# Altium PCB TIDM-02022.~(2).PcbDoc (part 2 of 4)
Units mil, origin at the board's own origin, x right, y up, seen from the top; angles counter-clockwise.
Board outline 1448.82 x 2299.21 mil, 16 copper layers (Top Layer, GND1, PWR1, PWR2, PWR3, GND2, GND3/SIG1, SIG2, SIG3, GND3/SIG4, GND5, PWR4, PWR5, GND6, GND7, Bottom Layer), stack 148.806 mil thick; 257 components, 138 nets, 739 pads, 1147 vias.

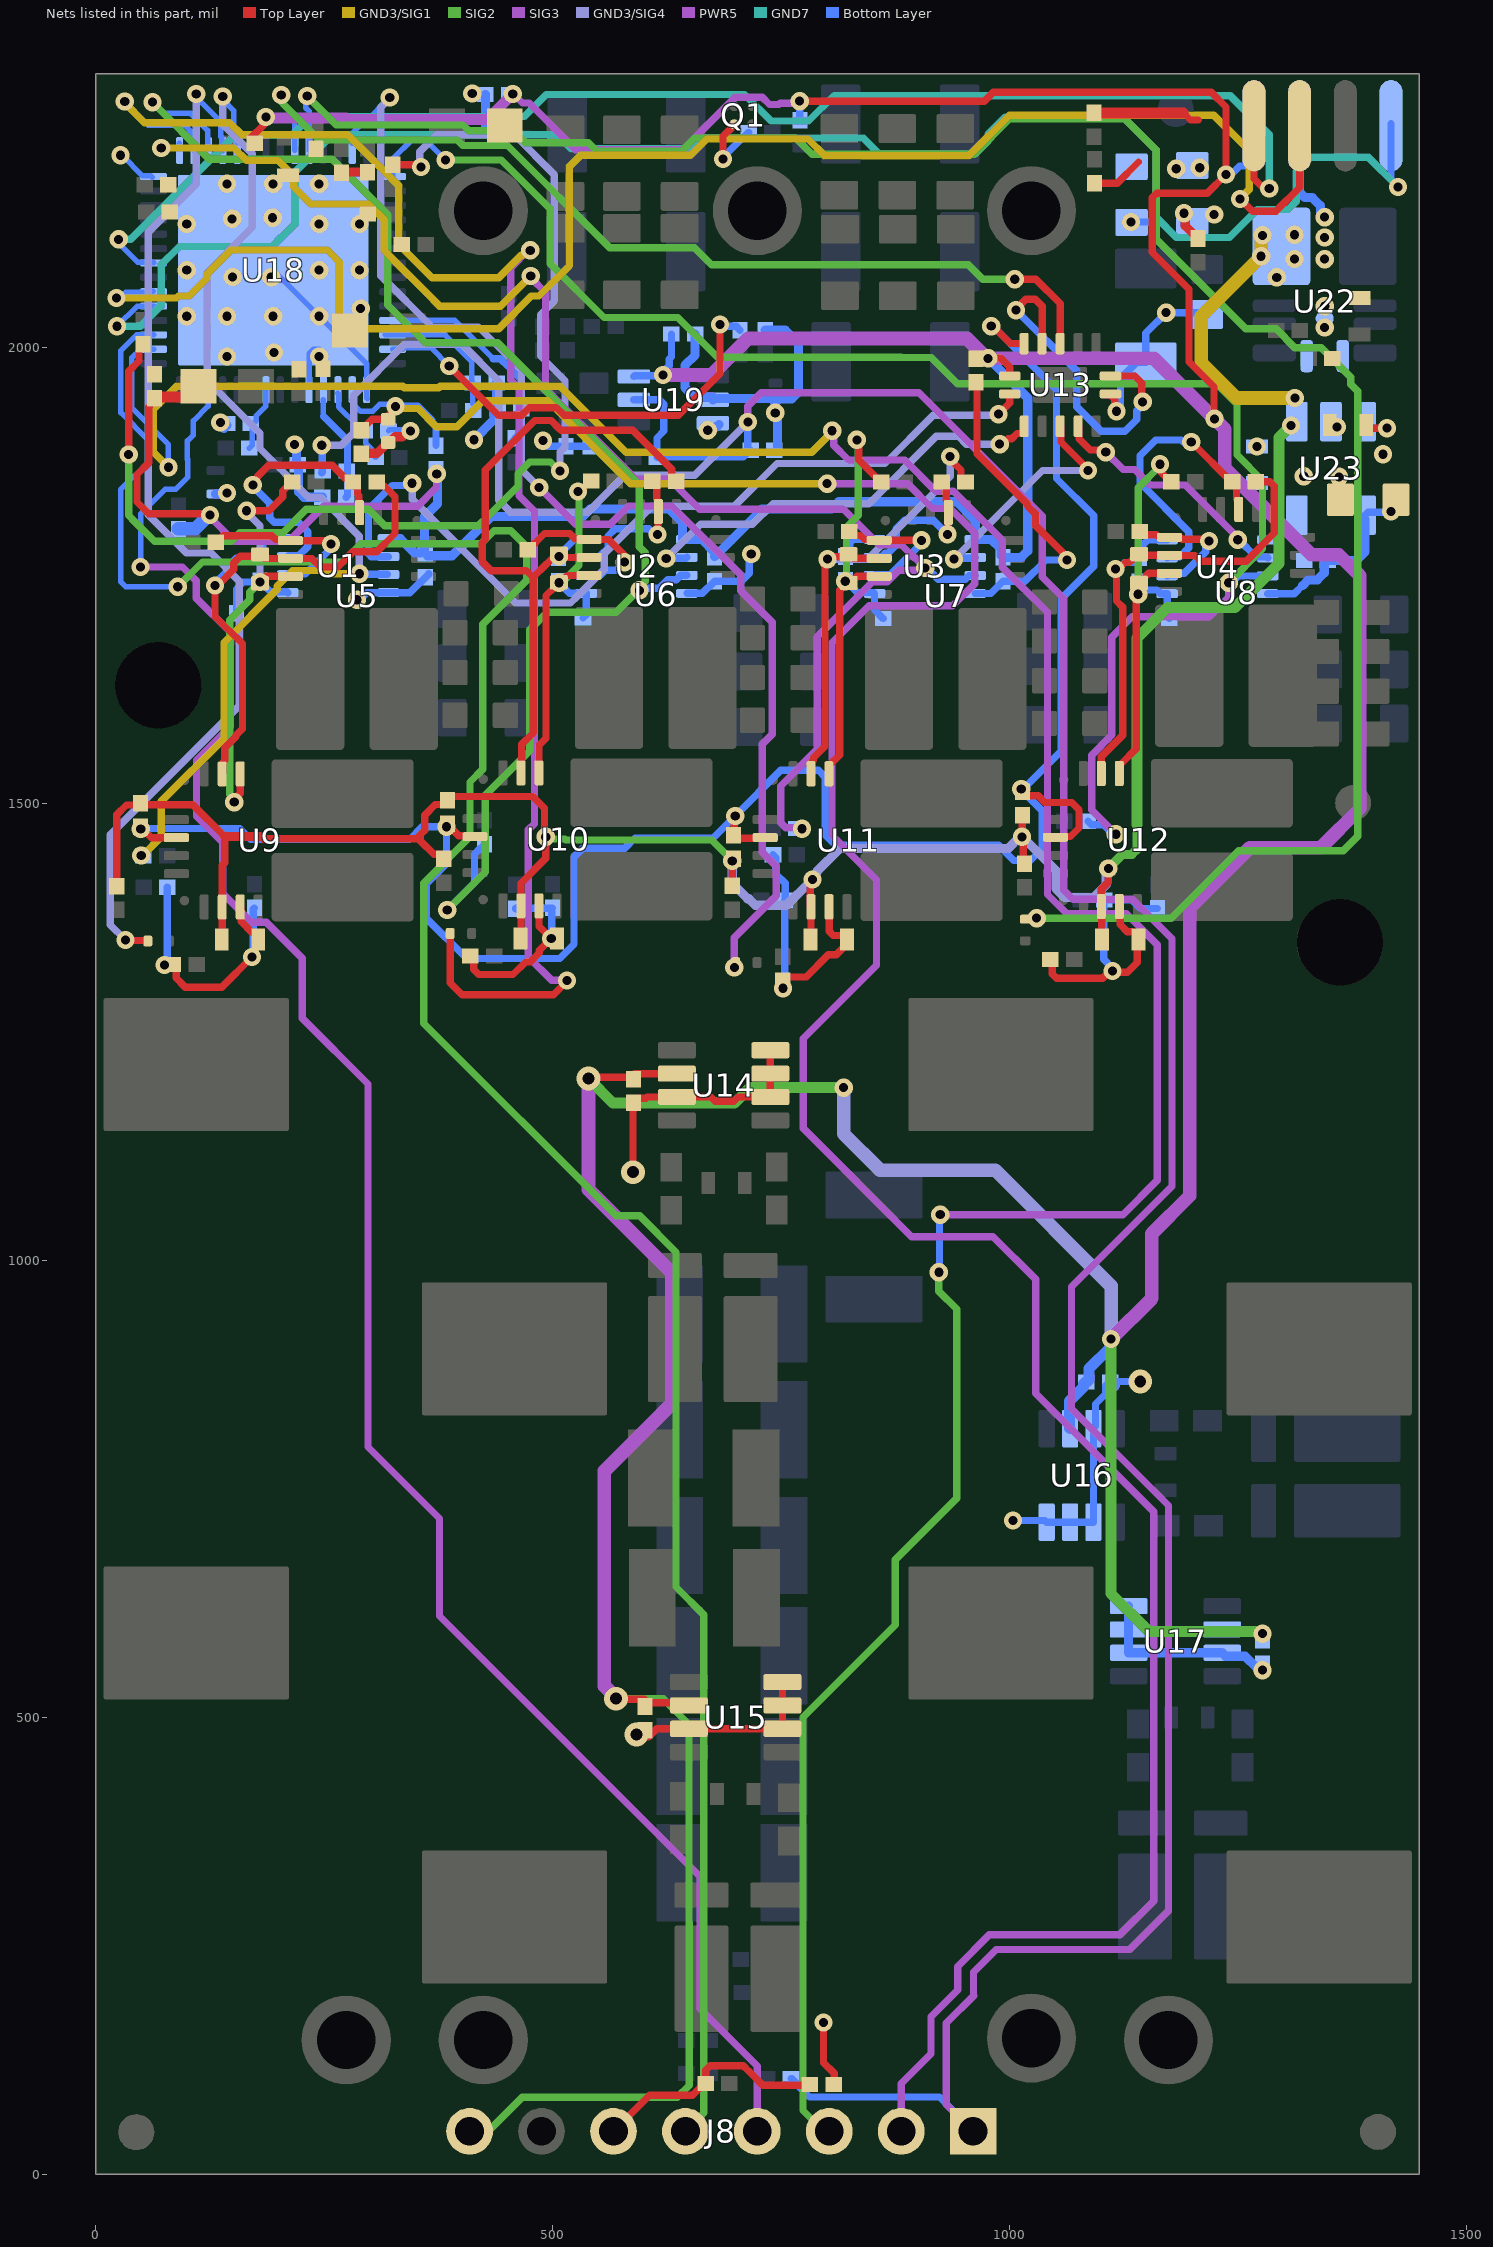
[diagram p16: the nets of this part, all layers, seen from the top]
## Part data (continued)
R33 R34 R35 R36 R41 R42 R43 R44: library part CMP-0025963-3, "RES, 10.0, 1%, 0.063 W, AEC-Q200 Grade 0, 0402", Manufacturer=Vishay-Dale, Power_W=63mW, Supplier Part Number 1=541-10.0LCT-ND, TempCo="100 ppm/C", Tolerance_%=1%, Value2=0.063W, Value_Code=10R0, ValueDisplayed=10.0
R37 R38 R39 R40: library part CMP-0083836-1, "RES, 100, 1%, 0.05 W, 0201", Manufacturer=Vishay-Semiconductor, Power_W=50mW, TempCo="100 ppm/C", Tolerance_%=1%, Value2=0.05W, Value_Code=100R, ValueDisplayed=100
R46: library part CMP-0026768-2, "RES, 100 k, 0.5%, 0.063 W, AEC-Q200 Grade 0, 0402", Manufacturer=Vishay-Dale, Power_W=63mW, Supplier Part Number 1=541-100KAVCT-ND, TempCo="50 ppm/C", Tolerance_%=0.5%, Value2=0.063W, Value_Code=100k
R47: library part CMP-0027657-1, "RES, 3.30 k, 1%, 0.05 W, 0201", Manufacturer="Yageo America", Power_W=50mW, Supplier Part Number 1=YAG2285CT-ND, TempCo="200 ppm/C", Tolerance_%=1%, Value2=0.05W, Value_Code=3k30, ValueDisplayed=3.30k
R49: library part CMP-0027789-1, "RES, 5.10 k, 1%, 0.05 W, 0201", Manufacturer="Yageo America", Power_W=50mW, Supplier Part Number 1=YAG2741CT-ND, TempCo="200 ppm/C", Tolerance_%=1%, Value2=0.05W, Value_Code=5k10, ValueDisplayed=5.10k
R55 R56 R58 R85 R86: library part CMP-0027995-1, "RES, 2.20 k, 1%, 0.05 W, 0201", Manufacturer="Yageo America", Power_W=50mW, Supplier Part Number 1=603-RC0201FR-7D2K2L, TempCo="200 ppm/C", Tolerance_%=1%, Value2=0.05W, Value_Code=2k20, ValueDisplayed=2.20k
R60: library part CMP-0027868-1, "RES, 768 k, 1%, 0.05 W, 0201", Manufacturer="Yageo America", Power_W=50mW, Supplier Part Number 1=YAG2796CT-ND, TempCo="200 ppm/C", Tolerance_%=1%, Value2=0.05W, Value_Code=768k
R61 R62: library part CMP-0027293-2, "RES, 100 k, 1%, 0.05 W, 0201", Manufacturer="Yageo America", Power_W=50mW, Supplier Part Number 1=311-100KMCT-ND, TempCo="200 ppm/C", Tolerance_%=1%, Value2=0.05W, Value_Code=100k
R65: library part CMP-0027793-1, "RES, 5.62 k, 1%, 0.05 W, 0201", Manufacturer="Yageo America", Power_W=50mW, Supplier Part Number 1=YAG2345CT-ND, TempCo="200 ppm/C", Tolerance_%=1%, Value2=0.05W, Value_Code=5k62, ValueDisplayed=5.62k
R66 R68: library part CMP-0027377-2, "RES, 15.0, 1%, 0.05 W, 0201", Manufacturer="Yageo America", Power_W=50mW, Supplier Part Number 1=311-15.0MCT-ND, TempCo="200 ppm/C", Tolerance_%=1%, Value2=0.05W, Value_Code=15R0, ValueDisplayed=15.0
R67: library part CMP-0027436-1, "RES, 1.43 k, 1%, 0.05 W, 0201", Manufacturer="Yageo America", Power_W=50mW, Supplier Part Number 1=YAG2481CT-ND, TempCo="200 ppm/C", Tolerance_%=1%, Value2=0.05W, Value_Code=1k43, ValueDisplayed=1.43k
R69: library part CMP-0027425-1, "RES, 1.13 k, 1%, 0.05 W, 0201", Manufacturer="Yageo America", Power_W=50mW, Supplier Part Number 1=YAG2471CT-ND, TempCo="200 ppm/C", Tolerance_%=1%, Value2=0.05W, Value_Code=1k13, ValueDisplayed=1.13k
R87: library part CMP-0027662-1, "RES, 3.60 k, 1%, 0.05 W, 0201", Manufacturer="Yageo America", Power_W=50mW, Supplier Part Number 1=YAG2651CT-ND, TempCo="200 ppm/C", Tolerance_%=1%, Value2=0.05W, Value_Code=3k60, ValueDisplayed=3.60k
R88: library part CMP-0126318-1, "22 kOhms ±0.5% 0.05W, 1/20W Chip Resistor 0201 (0603 Metric) Moisture Resistant Thick Film", Digikey Part Number=13-RC0201DR-0722KLCT-ND, Manufacturer=YAGEO, Mouser Part Number=603-RC0201DR-0722KL, Operating Temperature Range="-55°C to +125°C", Power_W=50mW, TempCo=200ppm/°C, Tolerance_%=0.5%
R91: library part CMP-0027792-1, "RES, 5.49 k, 1%, 0.05 W, 0201", Manufacturer="Yageo America", Power_W=50mW, Supplier Part Number 1=YAG2744CT-ND, TempCo="200 ppm/C", Tolerance_%=1%, Value2=0.05W, Value_Code=5k49, ValueDisplayed=5.49k
R92: library part CMP-0027939-1, "RES, 9.53 k, 1%, 0.05 W, 0201", Manufacturer="Yageo America", Power_W=50mW, Supplier Part Number 1=YAG2859CT-ND, TempCo="200 ppm/C", Tolerance_%=1%, Value2=0.05W, Value_Code=9k53, ValueDisplayed=9.53k
R93: library part CMP-0027453-1, "RES, 1.00 k, 1%, 0.05 W, 0201", Manufacturer="Yageo America", Power_W=50mW, Supplier Part Number 1=311-1KMCT-ND, TempCo="200 ppm/C", Tolerance_%=1%, Value2=0.05W, Value_Code=1k00, ValueDisplayed=1.00k
R94: library part CMP-0028000-1, "RES, 2.00 k, 1%, 0.05 W, 0201", Manufacturer="Yageo America", Power_W=50mW, Supplier Part Number 1=603-RC0201FR-7D2KL, TempCo="200 ppm/C", Tolerance_%=1%, Value2=0.05W, Value_Code=2k00, ValueDisplayed=2.00k
R95: library part CMP-0027973-1, "RES, 1.00 k, 1%, 0.05 W, 0201", Manufacturer="Yageo America", Power_W=50mW, Supplier Part Number 1=603-RC0201FR-7D1KL, TempCo="200 ppm/C", Tolerance_%=1%, Value2=0.05W, Value_Code=1k00, ValueDisplayed=1.00k
RT1: library part CMP-0123214-2, "±1% tolerance 10kΩ linear thermistor available in 0402 and 0603 package options 2-X1SON -40 to 125", Digikey Part Number=296-TMP6131DECRCT-ND, Manufacturer="Texas Instruments", Mouser Part Number=595-TMP6131DECR, Operating Temperature Range="-40°C to +125°C", Tolerance_%=1%
U1 U2 U3 U4: library part CMP-0123447-1, "General Purpose Dual-Channel Functional Isolators", Digikey Part Number=296-ISO6521FREURCT-ND, Manufacturer="Texas Instruments", Max Supply Voltage=5.5V, Min Supply Voltage=1.71V, Mouser Part Number=595-ISO6521FREUR, Operating Temperature Range="-40°C to +125°C"
U5 U6 U7 U8 U9 U10 U11 U12: library part CMP-0124166-1, Manufacturer="Texas Instruments", Operating Temperature Range=to
U13: library part CMP-0125756-1, "Four-channel two-input 1.65V to 3.6V AND gate 14-WQFN", Digikey Part Number=296-SN74LVC08ABQARCT-ND, Manufacturer="Texas Instruments", Max Supply Voltage=3.6V, Min Supply Voltage=1.65V, Mouser Part Number=595-SN74LVC08ABQAR, Nominal Supply Current=1uA, Operating Temperature Range="-40°C to +125°C"
U14 U15 U16 U17: library part CMP-0093651-2, "-4-V to 110-V, Bidirectional, Ultra-Precise Current Sense Amplifier With Enhanced PWM Rejection", Input Bias Current=40uA, Input Offset Voltage=0.002mV, Manufacturer="Texas Instruments", Max Supply Voltage=20V, Min Supply Voltage=2.7V, Nominal Supply Current=2.5mA, Operating Temperature Range="-40°C to +125°C", Voltage Gain=0.2V/mV
U18: library part CMP-0122591-1, "Real-Time Microcontrollers", Frequency_Fixed=150MHz, Manufacturer="Texas Instruments", Max Supply Voltage=3.63V, Min Supply Voltage=1.14V, Operating Temperature Range="-40°C to +150°C"
U19: library part CMP-0126255-1, "Low-power, 1-MΩ RIN, 20-µA IQ, small-size attenuating difference amplifier 6-SC70 -40 to 125", Digikey Part Number=296-INA500AIDCKRCT-ND, Manufacturer="Texas Instruments", Max Dual Supply Voltage=2.75V, Max Supply Voltage=5.5V, Min Dual Supply Voltage=850mV, Min Supply Voltage=1.7V, Mouser Part Number=595-INA500AIDCKR, Nominal Supply Current=13.5-14.5uA, Operating Temperature Range="-40°C to +125°C", Output Current Per Channel=33mA
U22: library part CMP-0098344-1, "3-V to 65-V Input, 1-V to 13-V Output, 600-mA Synchronous Buck Converter Power Module in a HotRod QFN Package", Manufacturer="Texas Instruments", Max Supply Voltage=65V, Min Supply Voltage=3.6V, Operating Temperature Range="-40°C to +125°C", Output Voltage=5V, Switching Frequency=1MHz
U23: library part CMP-0092532-1, "300-mA, Ultra-Low-Noise, Low-IQ, High PSRR LDO", Digikey Part Number=296-TPS7A2033PDBVRCT-ND, Dropout Voltage=145mV, Manufacturer="Texas Instruments", Max Supply Voltage=6V, Min Supply Voltage=1.6V, Mouser Part Number=595-TPS7A2033PDBVR, Nominal Supply Current=6.5uA, Operating Temperature Range="-40°C to +125°C", Output Voltage=3.3V

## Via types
v1: diameter 26, hole 13, Top Layer to Bottom Layer, tented both sides, 921 vias
v2: diameter 20, hole 10, Top Layer to Bottom Layer, tented both sides, 226 vias

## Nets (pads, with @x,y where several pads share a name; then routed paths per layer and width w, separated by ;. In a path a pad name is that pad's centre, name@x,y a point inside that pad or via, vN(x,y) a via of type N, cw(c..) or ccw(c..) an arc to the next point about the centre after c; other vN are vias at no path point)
3V3: 3V3.1 C49.1 C50.1 C51.1 C52.1 C81.1 C82.1 C83.1 C84.1 C94.1 C95.1 C124.1 C125.2 C147.1 C150.1 J8.8 L3.1 L4.1 R47.2 R55.2 R56.2 R87.2 U1.1 U2.1 U3.1 U4.1 U13.14 U14.6 U15.6 U16.6 U17.6 U19.6 U23.5 | length 8511.8
  Top Layer w8: C147.1@64.06,1944.15 59.8,1939.88 59.8,1936.23 57.98,1934.41 57.98,1873.42 45.21,1860.65 45.21,1830.43 58.1,1817.55 123.62,1817.55 v2(125.05,1816.12) ; R56.2@169.21,2228.56 v2@183.86,2243.21 ; v1(539.26,1199.37) 540.79,1200.91 586.55,1200.91 C81.1@588.75,1198.7 ; v1(569.56,520.58) 570.37,519.78 600.28,519.78 604,516.06 649.15,516.06 U15.6@649.25,515.96 ; C81.1@589.72,1204.74 U14.6@636.09,1204.74 ; v2(770.45,2269.26) 972.68,2269.26 982.55,2279.13 1220.99,2279.13 1237.17,2262.95 v2(1237.17,2188.94) 1216.8,2168.56 1161.18,2168.56 1156.5,2163.88 1156.5,2103.54 1196.69,2063.35 1196.69,1983.89 1223.96,1956.63 1223.96,1922.14 v2(1224.6,1921.5) ; v2@977.58,1988.13 990.66,1988.13 1000.51,1978.29 U13.14@1000.51,1968.45
  Top Layer w12: C147.1@64.06,1944.15 65.25,1945.34 109.77,1945.34 L3.1@114.37,1949.95 ; C95.1@963.51,1987.34 963.68,1987.52 976.61,1987.52 v2(976.79,1987.7)
  SIG3 w8: v2(125.05,1816.12) 125.05,1813.95 151.39,1787.61 211.21,1787.61 249.47,1825.88 352.35,1825.88 372.93,1846.46 372.93,1861.02 v2(373.21,1861.29) ; v2(456.46,2277.05) 457.24,2277.05 467.15,2267.14 474.49,2267.14 525.55,2216.08 642.66,2216.08 700.11,2273.53 729.52,2273.53 737.38,2265.67 747.6,2265.67 748.9,2266.97 768.15,2266.97 v2(770.45,2269.26)
  SIG3 w15: v1(539.26,1199.37) 539.26,1077.74 630.59,986.41 630.59,843.67 556.75,769.83 556.75,534.27 569.56,521.46 v1(569.56,520.58) ; v2(620.93,1969.38) 673.83,1969.38 713.82,2009.37 953.77,2009.37 975.44,1987.7 v2(976.79,1987.7) 1158.4,1987.7 v2(1224.6,1921.5) 1235.92,1910.18 1235.92,1867.49 1330.65,1772.76 1360.65,1772.76 1383.53,1749.88 1383.53,1494.62 1341.03,1452.12 1263.55,1452.12 1197.53,1386.1 1197.53,1071.1 1156.04,1029.61 1156.04,958.77 v2(1111.4,914.14)
  PWR5 w12: v2(186.16,2251.83) 187.21,2250.78 273.7,2250.78 275.41,2249.07 428.49,2249.07 v2(456.46,2277.05)
  SIG2 w8: J8.8@409.2,46.91 429.65,46.91 466.97,84.24 636.67,84.24 649.53,97.1 649.53,275.22 649.43,275.32 649.43,492.34 621.18,520.58 v1(569.56,520.58)
  SIG2 w12: v1(539.26,1199.37) 566.26,1172.37 699.33,1172.37 716.35,1189.39 v2(818.66,1189.39) ; v2(1111.4,914.14) 1111.4,635.46 1152.7,594.16 1269.01,594.16 1269.88,593.29 1275.54,593.29 v2(1277.07,591.76)
  GND3/SIG4 w15: v2(818.66,1189.39) 818.66,1138.97 858.53,1099.1 984.53,1099.1 1111.4,972.23 v2(1111.4,914.14)
  Bottom Layer w8: U19.6@588.94,1967.88 589.69,1968.63 620.18,1968.63 v2(620.93,1969.38) 620.93,1972.62 627.84,1979.54 627.84,1987.03 630.14,1989.33 C94.1@630.14,2014.26 ; v2(770.45,2269.26) 770.75,2268.97 770.75,2248.41 R55.2@771.04,2248.11 ; U17.6@1233,596.36 1272.47,596.36 v2(1277.07,591.76) ; v2@1241.57,2187.46 1252.33,2198.22 1256.67,2198.22 1267.8,2209.36 3V3.1@1267.8,2242.26
  Bottom Layer w10: U1.1@327.23,1790.23 333.45,1790.23 349,1774.68 C49.1@355.35,1774.68 ; R87.2@372.44,1858.78 374.02,1857.21 374.02,1828.61 359.85,1814.44 359.85,1775.02 363.21,1771.65 389.88,1771.65 432.85,1814.63 533.06,1814.63 541.05,1822.62 627.67,1822.62 642.33,1807.95 642.33,1790.44 643.25,1789.52 U2.1@647.07,1789.52 663.13,1789.52 C50.1@677.41,1775.24 ; C50.1@677.41,1770.64 729.38,1822.62 805.2,1822.62 813.29,1830.71 942.27,1830.71 962.68,1810.29 U3.1@962.68,1789.45 980.54,1789.45 990.75,1779.23 990.75,1772.05 C51.1@993.02,1769.79 1013.11,1769.79 1020.23,1776.9 1020.23,1944.27 v2(976.79,1987.7)
  Bottom Layer w12: U16.6@1066.49,816.09 1066.01,816.57 1066.01,846.41 1081.21,861.61 1081.21,865.05 1083.48,867.32 1085.06,867.32 1087.32,869.59 1087.32,881.88 v2@1109.87,904.43
  Bottom Layer w15: R47.2@90.44,1801.27 108.85,1801.27 123.7,1816.12 v2(125.05,1816.12)
  other v2: 1360.87,1858.03 1322.28,1858.71
5V: C66.1 C67.1 C68.1 C69.1 C121.2 C122.2 C123.1 R10.1 R12.1 R14.1 R16.1 R21.2 R22.2 R23.2 R24.2 R58.2 R62.1 U9.3 U10.3 U11.3 U12.3 U22.4 U22.9 U23.1 U23.3 | length 2925.2
  Top Layer w8: R10.1@22.9,1409.98 22.9,1488.03 33.63,1498.76 R21.2@44.95,1498.76 ; R21.2@47.83,1500.36 48.98,1499.21 106.2,1499.21 141.12,1464.3 141.12,1435.46 138.39,1432.73 U9.3@138.39,1387.23 138.39,1357.66 135.08,1354.36 C66.1@137.8,1351.63 ; 184.85,1461.85 350.6,1461.85 354.58,1465.83 355.33,1465.83 ; R12.1@380.84,1439.89 380.84,1440.67 376.58,1444.94 370.19,1444.94 355.33,1459.79 355.33,1465.83 ; R22.2@384.17,1502.91 380.53,1499.26 371.56,1499.26 360.04,1487.74 360.04,1471.29 355.33,1466.58 355.33,1465.83 ; R22.2@384.79,1504.19 388.69,1508.09 478.3,1508.09 491.25,1495.14 491.25,1465.21 v2(492.56,1463.89) 492.56,1440.43 465.45,1413.31 U10.3@465.45,1388.32 465.45,1358.75 462.14,1355.44 C67.1@464.86,1352.72 ; R14.1@696.76,1410.2 v2@696.76,1430.1 ; C68.1@782.93,1352.9 U11.3@782.93,1387.36 782.17,1388.12 782.17,1415.03 v2(784.46,1417.32) ; R16.1@1017.15,1435.28 1015.32,1437.11 1015.32,1462.56 v2(1013.99,1463.89) 1014.29,1464.2 1014.29,1482.35 1015.26,1483.31 R24.2@1017.69,1483.31 ; R58.2@1093.27,2179.45 1118.05,2179.45 1141.33,2202.73 ; U12.3@1100.69,1387.69 1100.69,1406.6 1108.36,1414.27 v2(1108.41,1429.34) v2(1108.41,1429.34) ; C69.1@1101.05,1352 U12.3@1101.05,1387.28 ; C123.1@1390.65,1914.81 1394.15,1911.31 v2(1413.45,1911.31)
  Top Layer w10: 141.12,1464.3 182.4,1464.3 184.85,1461.85 ; v2(1191.15,2146.56) 1192.59,2145.13 1192.59,2132.64 1202.27,2122.96 1203.06,2122.96 1206.33,2119.69 R62.1@1206.33,2118.9
  SIG2 w8: v2(492.56,1463.89) 494.86,1461.6 513.2,1461.6 514.39,1460.41 674.3,1460.41 696.73,1437.97 v2(696.73,1437.64)
  SIG2 w10: v2(1108.41,1429.34) 1123.83,1444.76 1134.14,1444.76 1140,1450.62 1140,1477.73
  SIG2 w12: 1139.55,1477.73 1139.55,1681.33 1173.16,1714.94 1246.91,1714.94 1295.19,1763.21 1295.19,1901.08 v2(1308.38,1914.27)
  GND3/SIG4 w10: v2(696.73,1437.64) 696.73,1412.91 713.5,1396.14 714.91,1396.14 722.05,1389 756.13,1389 v2@782.54,1415.41 ; v2(784.46,1417.32) 784.46,1420.03 789.46,1425.03 789.46,1426.3 814.26,1451.1 998.49,1451.1 1011.28,1463.89 v2(1013.99,1463.89) ; v2@1014.32,1463.89 1050.95,1427.26 1050.95,1407.35 1060.91,1397.38 1091.87,1397.38 1106.11,1411.62 1106.11,1427.04 v2(1108.41,1429.34)
  GND3/SIG1 w15: v2(1277.07,2122.36) 1275.68,2120.98 v2(1275.68,2099.45) 1210.06,2033.83 1210.06,1982.56 1248.38,1944.24 v2(1312.57,1944.24)
  Bottom Layer w8: C122.2@1134.83,2136.99 1158.56,2136.99
  other v2: 1408.93,1882.69 1292.73,2076.34 1312.1,2096.46 1312.1,2123.06 1133.19,2137.09 1224.22,2145.28
+3V3_MCU: R85.2 R86.2 | length 1305.6
  Top Layer w8: v2(35.98,1882.53) 35.98,1973.52 47.22,1984.76 47.22,1998.9 R85.2@51.49,2003.16 ; R86.2@325.04,2199.61 v2@356,2199.61
  SIG2 w8: v2(35.98,1882.53) 35.98,1815.78 42.82,1808.94 64.23,1787.53 148.13,1787.53 157.42,1796.83 204.85,1796.83 230.41,1822.38 298.47,1822.38 316.36,1804.49 418.75,1804.49 429.31,1815.05 429.54,1815.05 462.15,1847.66 462.15,1861.29 475.03,1874.18 497.84,1874.18 507.49,1864.53 v2(508.17,1864.53)
  GND3/SIG4 w8: v2(356,2197.24) 354.51,2198.72 354.51,2213.84 373.08,2232.4 458.41,2232.4 501.97,2188.85 501.97,2050.5 486.86,2035.39 486.86,1990.22 513.53,1963.56 513.53,1890.52 508.17,1885.16 v2(508.17,1864.53)
ADDR0: C98.1 J8.2 R87.1 R88.2 U18.16 | length 3231.2
  Top Layer w8: C98.1@290.58,1909.2 290.58,1909.99 294.85,1914.26 295.63,1914.26 302.58,1921.2 R88.2@320.17,1921.2 ; R88.2@317.82,1922.57 328.15,1932.89 v2(328.15,1935.14)
  SIG3 w8: v2(800.61,1850.55) 888.67,1850.55 915.82,1823.4 935.18,1823.4 962,1796.57 962,1740.87 937.87,1716.74 846.39,1716.74 805.9,1676.25 805.9,1465.72 854.63,1416.99 854.63,1323.46 774.33,1243.16 774.33,1144.79 892.85,1026.27 982.05,1026.27 1028.82,979.5 1028.82,854.62 1158.16,725.28 1158.16,299.14 1121.02,262 978,262 943.45,227.45 943.45,201.67 914.23,172.45 914.23,131.95 881.64,99.36 J8.2@881.64,46.91
  GND3/SIG1 w8: v2(328.15,1935.14) 330.44,1932.85 352.85,1932.85 372.76,1912.94 395.31,1912.94 423.59,1941.22 494.92,1941.22 585.59,1850.55 v2(800.61,1850.55)
  Bottom Layer w6: U18.16@280.81,1942.59 281.68,1941.72 281.68,1937.89 289.98,1929.59 303,1929.59 310.74,1937.32 v2@328.15,1937.32
  Bottom Layer w8: v2(328.15,1935.14) 352.6,1935.14 367.94,1919.8 367.94,1918.16 372.44,1913.66 R87.1@372.44,1892.25
AGND_RS-: J8.6 R51.1 R70.1 | length 265.1
  Top Layer w8: J8.6@566.68,46.91 606.05,86.29 653.09,86.29 663.44,96.63 663.44,97.42 667.71,101.69 R51.1@668.49,101.69 ; R51.1@668.34,99.47 R51.1@667.68,99.47 667.68,114.08 672.37,118.77 708.66,118.77 714.41,113.02 714.61,113.02 730.21,97.42 R70.1@781.76,97.42
ALERT: J8.4 U18.26 | length 2290.7
  SIG3 w8: v2(49.04,1759.35) 94.96,1759.35 109.97,1744.34 109.97,1725.27 147.04,1688.19 147.04,1584.82 110.31,1548.09 110.31,1486.58 139.01,1457.88 139.01,1401.89 170.46,1370.45 186.73,1370.45 226,1331.17 226,1265.4 298,1193.4 298,804.52 298,796.03 376.18,717.85 376.18,611.08 661.42,325.84 661.42,181.17 724.16,118.43 J8.4@724.16,46.91
  Bottom Layer w6: v2(49.04,1759.35) 49.04,1817.56 76.09,1844.61 87.77,1844.61 100.54,1857.38 100.54,1877.24 100.3,1877.48 100.3,1897.32 106.74,1903.76 106.74,1919.25 122.92,1935.43 122.92,1953.01 U18.26@123.26,1953.35
CLK: J8.3 U18.30 | length 3432.9
  SIG3 w8: v2(806.06,1908.4) 807.74,1906.71 807.74,1892.73 824.01,1876.46 885.39,1876.46 919.5,1842.35 938.85,1842.35 992.37,1788.83 992.37,1759.12 1041.8,1709.69 1041.8,1400.91 1063.05,1379.67 1128.24,1379.67 1162.03,1345.88 1162.03,1087.95 1124.47,1050.4 v2(924.37,1050.4)
  SIG2 w8: J8.3@802.9,46.91 796.91,46.91 774.09,69.73 774.09,500.28 875.03,601.22 875.03,672.51 942.32,739.8 942.32,947.15 922.85,966.62 v2(922.85,987.39)
  GND3/SIG1 w8: v2(79.54,1868.54) 63.13,1884.95 63.13,1931.65 88.62,1957.14 336.24,1957.14 337.71,1955.67 375.29,1955.67 376.9,1957.28 508.11,1957.28 580.36,1885.02 783.85,1885.02 806.06,1907.23 v2(806.06,1908.4)
  Bottom Layer w6: U18.30@63.22,1997.64 48.7,1997.64 39.46,1988.41 39.46,1933.29 79.54,1893.21 v2(79.54,1868.54)
  Bottom Layer w8: v2(922.85,987.39) 923.61,988.15 923.61,1049.64 v2(924.37,1050.4)
DACA: R94.1 U18.13 | length 494.1
  Top Layer w8: v2(386.88,1979.28) 440.89,1925.27 466.26,1925.27 474.59,1933.61 504.41,1933.61 512.75,1925.27 637.63,1925.27 683.23,1970.87 v2(683.23,2024.81)
  Bottom Layer w6: U18.13@325.04,1997.64 335.86,1997.64 337.67,1999.46 366.71,1999.46 v2(386.88,1979.28)
  Bottom Layer w8: v2(683.23,2024.81) 685.31,2022.73 700.95,2022.73 705.22,2018.46 R94.1@705.22,2018.4
DATA: J8.5 U18.31 | length 2732.4
  SIG2 w8: v2(89.72,1737.72) 116.82,1764.83 270.32,1764.83 290.26,1784.77 421.66,1784.77 435.94,1799.05 454.16,1799.05 471.74,1781.47 471.74,1744.79 423.69,1696.74 423.69,1538.01 409.67,1523.99 409.67,1463.89 359.07,1413.3 359.07,1259.56 569.56,1049.07 595.43,1049.07 635.14,1009.36 635.14,642.81 665.43,612.53 665.43,281.95 665.53,281.85 665.53,67.02 J8.5@645.42,46.91
  Bottom Layer w6: U18.31@63.22,2013.39 44.65,2013.39 27.46,1996.21 27.46,1928.32 57.89,1897.88 57.89,1876.93 56.98,1876.01 56.98,1873.83 27.15,1844 27.15,1743.25 32.67,1737.72 v2(89.72,1737.72)
EPWM1A: R96.2 U1.3 U18.47 | length 1177
  GND3/SIG4 w8: v2(139.01,2274.26) 139.01,2243.69 171.12,2211.58 171.12,2149.71 171.28,2149.55 171.28,2131.33 121.89,2081.95 121.89,2043.14 121.74,2042.98 121.74,2024.75 121.89,2024.59 121.89,1999.04 121.74,1998.88 121.74,1980.66 121.89,1980.5 121.89,1963.57 179.68,1905.78 179.68,1888.93 233.27,1835.34 246.32,1835.34 288.55,1793.11 v2(288.55,1751.95)
  GND3/SIG1 w8: v2(49.76,1443.4) 51.22,1443.4 71.69,1463.87 71.69,1502.78 140.39,1571.48 140.39,1676.55 198.79,1734.96 198.79,1738.61 215.63,1755.45 255.05,1755.45 258.55,1751.95 v2(288.55,1751.95)
  Bottom Layer w6: v2(139.01,2274.26) 139.01,2270.84 151.16,2258.69 151.16,2240.18 154.76,2236.57 U18.47@154.76,2223.6
  Bottom Layer w8: v2(288.55,1751.95) 289.06,1751.44 318.89,1751.44 U1.3@319.07,1751.25
EPWM1B: R9.1 U18.46 | length 1167.5
  Top Layer w8: v2(32.49,1350.99) 33.05,1350.42 55.18,1350.42 R9.1@55.74,1350.99
  GND3/SIG4 w8: v2(32.49,1350.99) 16,1367.48 16,1466.35 157,1607.35 157,1743.84 126.1,1774.74 99.16,1774.74 57.53,1816.38 57.53,2125.82 109.95,2178.25 v2(109.95,2276.97)
  Bottom Layer w6: v2(109.95,2276.97) 109.95,2273.62 137.04,2246.53 137.04,2230.44 138.07,2229.41 138.07,2216.1 U18.46@139.01,2215.16
EPWM2A: R97.2 U2.3 U18.45 | length 1600
  SIG2 w8: v2(61.99,2268.12) 124.36,2205.76 258.8,2205.76 319.7,2144.86 319.7,2046.06 360.95,2004.81 439.9,2004.81 595.07,1849.64 595.07,1781.47 601.53,1775.01 601.53,1743.46 595.07,1737 v2(595.07,1733.75) 593.86,1733.75 569.8,1709.69 494.11,1709.69 475.03,1690.61 475.03,1558.07 426.31,1509.35 426.31,1425.48 v2@386.88,1386.05
  Bottom Layer w6: v2(61.99,2268.12) 74.15,2255.97 103.87,2255.97 122.45,2237.38 122.45,2223.98 U18.45@122.83,2223.6
  Bottom Layer w8: v2(384.68,1383.85) 414.61,1413.78 414.61,1445.23 420.36,1450.98 421.15,1450.98 425.41,1455.25 R97.2@425.41,1456.04 ; v2(595.07,1733.75) 597.36,1736.04 616.61,1736.04 625.95,1745.38 635.41,1745.38 640.18,1750.15 U2.3@647.07,1750.15
EPWM2B: R11.1 U18.44 | length 1729.3
  Top Layer w8: R11.1@387.9,1358.16 387.9,1303.99 400.94,1290.95 501,1290.95 515.75,1305.7 v2(515.75,1306.8)
  SIG3 w8: v2@474.83,2107.74 454.1,2087.01 454.1,1963.95 463.36,1954.68 463.36,1837.14 480.21,1820.29 480.21,1478.41 473.56,1471.76 473.56,1332.4 499.16,1306.8 v2(515.75,1306.8) ; v2@515.75,1311 v2@517.08,1311
  GND3/SIG1 w8: v2(31.65,2268.79) 31.65,2267.35 53.42,2245.58 146.44,2245.58 159.62,2232.4 275.99,2232.4 331.62,2176.76 331.62,2112.38 340.95,2103.05 368,2076 441,2076 465.7,2100.7 467.15,2100.7 472.36,2105.91 v2(475.61,2105.91)
  Bottom Layer w6: v2(31.65,2268.79) 57.36,2243.06 96.98,2243.06 106.7,2233.33 106.7,2215.98 U18.44@107.52,2215.16
EPWM3A: R98.2 U3.3 U18.43 | length 1631.6
  SIG3 w8: v2@476.1,2075.85 492.18,2059.76 492.18,1954.7 591.37,1855.51 627.98,1855.51 660.87,1822.62 818.46,1822.62 857.69,1783.4 882.01,1783.4 895.92,1769.49 897.15,1769.49 907.84,1758.8 v2(907.84,1758.32) 905.54,1756.03 897.4,1756.03 897.15,1755.78 879.1,1755.78 866.29,1742.98 850,1742.98 789.9,1682.88 789.9,1559.81 749.69,1519.61 749.69,1479.7 755.34,1474.06 v2@775.23,1474.06
  GND3/SIG1 w8: v2(71.69,2218) 151.39,2218 165.12,2204.27 199.72,2204.27 216.85,2187.14 216.85,2175.31 235.41,2156.75 298.2,2156.75 315.62,2139.33 315.62,2105.75 325.56,2095.82 361.37,2060 376.6,2044.77 442.97,2044.77 v2(476.1,2077.9)
  Bottom Layer w6: v2(71.69,2218) 90.83,2218 91.33,2218.5 U18.43@91.33,2223.39
  Bottom Layer w8: R98.2@767.59,1475.22 768.38,1475.22 772.65,1470.95 R98.2@772.65,1470.47 ; v2@908.86,1759.35 922.28,1745.93 951.65,1745.93 955.79,1750.08 U3.3@962.68,1750.08
  other v2: 773.16,1472.74
EPWM3B: R13.1 U18.55 | length 1351.5
  SIG3 w8: v2(485.36,1846.25) 525.49,1806.12 563.26,1806.12 583.17,1826.02 630.58,1826.02 705.93,1750.67 705.93,1733.2 740.38,1698.76 740.38,1576.13 729.69,1565.45 729.69,1446.95 745.02,1431.61 745.02,1399.55 699.03,1353.56 v2(699.03,1320.98)
  GND3/SIG4 w8: v2(321.74,2273.37) 321.74,2272.63 311.78,2262.68 311.78,2078.22 368,2022 419,2022 466,1975 466,1865.61 v2(485.36,1846.25)
  Bottom Layer w6: U18.55@280.74,2223.16 281.68,2224.1 281.68,2234.77 293.04,2246.13 294.51,2246.13 v2(321.74,2273.37)
EPWM4A: R99.2 U4.3 U18.1 | length 1811.2
  SIG3 w8: v2(1116.58,1466.76) 1090.07,1493.26 1090.07,1553.25 1112.21,1575.39 1112.21,1682.59 1134.37,1704.75 1218.83,1704.75 1240.16,1726.09 v2(1240.16,1742.13)
  SIG2 w8: v2(382.98,2204.76) 443.98,2204.76 497.61,2151.13 497.61,2091.21 556.36,2032.45 636.97,2032.45 680.48,1988.94 881.69,1988.94 882.06,1988.57 914.47,1988.57 943.29,1959.75 1226.87,1959.75 1249.19,1937.44 1249.19,1882.1 1277.19,1854.1 1277.19,1779.16 v2(1240.16,1742.13)
  Bottom Layer w6: U18.1@325.04,2186.62 325.04,2205.73 347.94,2228.63 359.25,2228.63 359.25,2228.48 v2(382.98,2204.76)
  Bottom Layer w8: R99.2@1086.05,1481.05 1090.05,1477.06 1103.03,1477.06 1113.33,1466.76 v2(1116.58,1466.76) ; v2(1240.16,1742.13) 1243.41,1742.13 1250.72,1749.44 1282.69,1749.44 U4.3@1282.98,1749.73
EPWM4B: R15.1 U18.52 | length 2330.9
  Top Layer w8: R15.1@1017.51,1373.76 1018.1,1374.35 1029.35,1374.35 v2(1029.94,1374.94)
  SIG2 w8: v2(231.5,2274.78) 263.19,2243.1 402.01,2243.1 408.35,2236.76 457.24,2236.76 470.26,2223.74 539.41,2223.74 548.44,2214.7 641.28,2214.7 655.48,2228.89 766.26,2228.89 784.06,2211.1 961.5,2211.1 1000.24,2249.84 1126.41,2249.84 1160.79,2215.46 1160.79,2117.95 1258.77,2019.97 1292.05,2019.97 1312.59,1999.42 1341.43,1999.42 1373.84,1967.01 1373.84,1959.31 1381.53,1951.62 1381.53,1464.59 1365.5,1448.56 1250.81,1448.56 1177.19,1374.94 v2(1029.94,1374.94)
  Bottom Layer w6: v2@229.85,2266.54 229.85,2261.99 233.58,2258.25 U18.52@233.58,2215.25
FLT1T: R1.2 U1.7 U5.13 | length 299.7
  Top Layer w8: v2(171.95,1849.1) 171.95,1852.35 177.35,1857.75 177.35,1858.81 189.18,1870.64 258.91,1870.64 273.1,1856.45 278.04,1856.45 286.45,1848.04 286.45,1838.94 287.86,1837.54 287.86,1819.83 U5.13@288.78,1818.91
  Bottom Layer w8: v2(171.95,1849.1) 171.95,1847.58 190.5,1829.03 190.5,1813.09 195.19,1808.41 221.81,1808.41 232,1798.22 232,1781.63 221.91,1771.54 211.11,1771.54 U1.7@210.19,1770.62
FLT1T-LS: U1.2 U13.1 | length 964
  Top Layer w8: v2@990.66,1929.08 v2(988.22,1926.64) 1000.51,1938.92 U13.1@1000.51,1948.76
  GND3/SIG4 w8: v2(346.29,1850.93) 346.29,1833.49 459.78,1720 519.73,1720 527,1727.27 556.65,1756.92 556.65,1773.74 608.61,1825.7 698.93,1825.7 745.79,1872.55 863.99,1872.55 916.71,1925.27 986.86,1925.27 v2(988.22,1926.64)
  Bottom Layer w8: U1.2@320.42,1770.62 301.57,1770.62 298.55,1773.64 298.55,1822.45 324.74,1848.63 343.99,1848.63 v2(346.29,1850.93)
FLT2T: R2.2 U2.7 U6.13 | length 160.9
  Top Layer w8: R2.2@610.14,1853.19 614.18,1849.15 614.18,1833.35 614.91,1832.62 614.91,1820.92 U6.13@615.84,1820 615.4,1819.57 615.4,1795.39 v2(614.97,1794.96)
  Bottom Layer w8: U2.7@536.83,1769.83 537.75,1770.75 547.49,1770.75 551.3,1770.75 552.58,1772.03 ; 553.15,1772.6 560.64,1780.09 ; 560.64,1780.89 560.64,1793.27 568.7,1801.33 605.36,1801.33 611.73,1794.96 v2(614.97,1794.96)
FLT2T-LS: U2.2 U13.2 | length 485.9
  Top Layer w8: v2(989.39,1893.77) 992.63,1893.77 998.47,1899.61 1002.53,1899.61 1008.44,1905.52 1015.33,1905.52 1016.25,1906.44 U13.2@1016.25,1913.33
  GND3/SIG4 w8: v2(624.51,1768.56) 661.95,1806 718.89,1806 741.44,1828.55 846.31,1828.55 920.1,1902.35 944.35,1902.35 952.93,1893.77 v2(989.39,1893.77)
  Bottom Layer w8: v2(624.51,1768.56) 624.86,1768.91 646.15,1768.91 U2.2@647.07,1769.83
FLT3T: R3.2 U3.7 U7.13 | length 174.6
  Top Layer w8: R3.2@926.06,1852.31 926.62,1852.31 930.89,1848.04 930.89,1832.82 932.39,1831.32 932.39,1819.96 U7.13@933.32,1819.04 932.86,1818.59 932.86,1795.5 v2(932.41,1795.05)
  Bottom Layer w8: U3.7@852.45,1769.76 853.37,1770.68 860.26,1770.68 864.1,1774.52 867.25,1774.52 876.26,1783.54 876.26,1801.24 885.5,1810.49 916.73,1810.49 932.17,1795.05 v2(932.41,1795.05)
FLT3T-LS: U3.2 U13.4 | length 272
  Top Layer w8: U13.4@1055.62,1913.33 1056.55,1912.41 1056.55,1896.21 1086.11,1866.65 v2(1086.11,1864.86)
  GND3/SIG4 w8: v2(939.39,1767.93) 1036.32,1864.86 v2(1086.11,1864.86)
  Bottom Layer w8: v2(939.39,1767.93) 940.31,1768.85 961.77,1768.85 U3.2@962.68,1769.76
FLT4T: R4.2 U4.7 U8.13 | length 314.9
  Top Layer w8: v2(1199.21,1896.23) 1199.4,1896.23 1243.03,1852.6 1244.48,1852.6 1248.75,1848.33 1248.75,1833.51 1250.15,1832.11 1250.15,1820.25 U8.13@1251.08,1819.33
  Bottom Layer w8: U4.7@1172.74,1769.41 1173.66,1770.34 1186.53,1770.34 1196.55,1780.36 1196.55,1797.84 1142.95,1851.44 1142.95,1880.93 1160.43,1898.41 1188.34,1898.41 1190.52,1896.23 v2(1199.21,1896.23)
FLT4T-LS: U4.2 U13.5 | length 276.3
  Top Layer w8: U13.5@1075.31,1913.33 1076.23,1912.41 1076.23,1899.55 1088.46,1887.32 1103.25,1887.32 v2(1105.55,1885.02)
  SIG3 w8: v2(1105.55,1885.02) 1124.62,1865.95 1137.43,1865.95 1154.2,1849.18 1192.53,1849.18 1250.03,1791.67 v2(1250.03,1789.16)
  Bottom Layer w8: v2(1250.03,1789.16) 1251.18,1789.16 1270,1770.34 1282.06,1770.34 U4.2@1282.98,1769.41
FLTB: R21.1 R22.1 R23.1 R24.1 U9.13 U10.13 U11.13 U12.13 U13.13 | length 2349.8
  Top Layer w8: R21.1@49.21,1473.23 49.21,1472.44 53.48,1468.17 55.75,1468.17 60.9,1463.02 U9.13@88.19,1463.02 ; v2(383.86,1474.94) 383.86,1477.27 R22.1@384.79,1478.21 ; R22.1@384.79,1477.42 397.19,1465.03 U10.13@413.39,1465.03 ; v2@698.82,1482.02 698.82,1465.97 702.27,1462.52 732.11,1462.52 U11.13@732.73,1463.15 ; v2(699.94,1486.85) 700.35,1486.43 v2@700.35,1482.02 ; v2(980.22,2022.95) 982.07,2022.95 1001.13,2003.88 U13.13@1016.25,2003.88 ; v2(1013.05,1516.39) 1013.05,1514.93 R24.1@1014.6,1513.39 1014.6,1512.6 1018.26,1508.95 1031.54,1508.95 1038.87,1501.62 1068.32,1501.62 1076.27,1493.67 1076.27,1473.69 1066.94,1464.36 1041.93,1464.36 U12.13@1040.94,1463.37
  Bottom Layer w8: v2(49.2,1472.49) 49.71,1473.01 157.5,1473.01 169.44,1461.06 343.43,1461.06 357.31,1474.94 v2(383.86,1474.94) 383.86,1434.3 361.86,1412.3 361.86,1374.91 406.05,1330.72 507.75,1330.72 523.58,1346.55 523.58,1442.08 533.01,1451.51 579.11,1451.51 590.25,1462.65 597.13,1462.65 ; 597.19,1462.65 675.74,1462.65 v2(699.94,1486.85) 749.8,1536.71 791.1,1536.71 798.64,1529.16 798.64,1466.06 810.13,1454.58 988.3,1454.58 995.01,1447.87 ; v2(980.22,2022.95) 982.07,2022.95 1051.7,1953.31 1051.7,1856.24 1092.27,1815.67 1092.27,1795.44 1092.27,1759.98 1056.73,1724.43 1056.73,1557.98 1015.14,1516.39 v2(1013.05,1516.39) 1013.05,1515.52 1035.99,1492.58 1035.99,1450.93 1023.1,1438.04 1004.88,1438.04 995.04,1447.87
FLTGAN: U13.11 U18.51 | length 1062.4
  Top Layer w8: v2(1005.98,2074.35) 1028.94,2074.35 1055.63,2047.65 U13.11@1055.62,2003.88
  SIG2 w8: v2(203.03,2276.09) 205.33,2273.8 205.33,2266.07 244.64,2226.76 395.73,2226.76 401.73,2220.76 450.61,2220.76 562.47,2108.9 655.31,2108.9 674.05,2090.16 955.2,2090.16 971.01,2074.35 v2(1005.98,2074.35)
  Bottom Layer w6: v2(203.03,2276.09) 203.03,2267.58 217.63,2252.98 U18.51@217.63,2215.29
FLTT: U13.8 U13.12 | length 372.8
  Top Layer w8: v2(1007.4,2040.45) 1007.4,2041.66 1018.09,2052.35 1028.31,2052.35 1035.94,2044.71 U13.12@1035.94,2003.88 ; U13.8@1110.74,1968.45 1137.16,1968.45 1144.98,1960.63 v2@1144.98,1941.06
  Bottom Layer w8: v2(1007.4,2040.45) 1073.65,1974.2 1073.65,1934.67 1100.53,1907.8 1126.53,1907.8 1139.42,1920.69 1139.42,1930.35 1145.93,1936.86 v2(1145.93,1940.11)
GND: C49.2 C50.2 C51.2 C52.2 C66.2 C67.2 C68.2 C69.2 C70.2 C71.2 C72.2 C73.2 C81.2 C82.2 C83.2 C84.2 C89.2 C90.2 C91.2 C92.2 C93.2 C94.2 C95.2 C96.1 C97.2 C98.2 C103.2 C106.2 C114.2 C118.1 C119.1 C120.2 C121.1 C122.1 C123.2 C124.2 C125.1 C143.2 C144.2 C145.2 C146.2 C147.2 C148.2 C149.2 C150.2 C151.2 C152.2 C153.2 C154.2 C155.1 GND.1 NT1.1 Q1.A2 R49.1 R61.1 R70.2 R75.1 R76.1 R77.1 R78.1 R79.1 R80.1 R81.1 R82.1 R88.1 R92.1 R95.1 RT1.1 U1.4 U2.4 U3.4 U4.4 U9.4 U10.4 U11.4 U12.4 U13.7 U14.2 U14.3 U14.4 U14.7 U15.2 U15.3 U15.4 U15.7 U16.2 U16.3 U16.4 U16.7 U17.2 U17.3 U17.4 U17.7 U18.15 U18.19 U18.42 U18.57 U19.2 U19.3 U22.10 U22.11 U23.2 U23.4 | length 4610.9
  Top Layer w8: v2(75.28,1323.76) 75.35,1323.7 C70.2@81.31,1323.7 ; C70.2@84.34,1324.08 87.97,1320.45 87.97,1309.42 97.99,1299.4 137.94,1299.4 v2(170.99,1332.45) ; U9.4@158.08,1387.23 159,1386.31 159,1371.48 170.84,1359.63 174.3,1359.63 177.8,1356.13 C66.2@177.8,1351.63 174.3,1348.13 v2@174.3,1339.01 ; C155.1@279.48,2004.09 289.94,2014.55 C155.1@289.94,2035 ; C71.2@410.01,1333.44 413.57,1329.88 413.57,1318.71 419.11,1313.18 456.8,1313.18 470.62,1327 475.61,1327 485.36,1336.75 485.36,1339.44 v2(498.64,1352.72) 485.13,1366.23 U10.4@485.13,1388.32 ; v1(588.08,1096.92) 588.08,1165.03 C81.2@588.75,1165.7 ; C81.2@588.75,1172.71 588.75,1173.37 593.02,1177.64 601.99,1177.64 603.5,1179.15 U14.7@636.09,1179.15 673.01,1179.15 677.79,1174.37 698.5,1174.37 703.28,1179.15 U14.2@738.45,1179.15 U14.3@738.45,1204.74 U14.4@738.45,1230.33 ; v1(591.92,481.26) 594.21,478.98 605.58,478.98 614.16,487.55 U15.7@649.25,487.55 U15.2@751.62,487.55 ; v2(686.6,2205.9) 686.6,2230.68 698.35,2242.42 698.35,2243.5 Q1.A2@698.89,2244.05 ; U15.2@751.62,490.37 U15.3@751.62,513.14 U15.4@751.62,538.73 ; C72.2@756.03,1310.59 777.63,1310.59 801.84,1334.79 810.52,1334.79 818.84,1343.11 818.84,1343.76 C68.2@820.26,1345.18 ; v2(796.65,165.96) 796.65,122.04 808.28,110.4 R70.2@808.28,98.13 ; U11.4@802.73,1385.7 802.73,1360.57 807.42,1355.88 818.84,1355.88 C68.2@822.34,1352.38 ; C95.2@963.51,1961.36 964.57,1960.29 964.57,1883.33 1019.94,1827.95 1019.94,1825.99 1028.98,1816.95 1028.98,1804.59 1057.3,1776.27 1057.3,1776.18 1063.18,1770.29 v2(1063.18,1767.04) ; C73.2@1044.86,1329.66 1047.08,1327.43 1047.08,1313.81 1051.77,1309.13 1102.2,1309.13 1110.11,1317.03 v2(1112.89,1317.03) 1114.29,1315.64 1129.43,1315.64 1140.12,1326.33 C69.2@1140.12,1352.03 ; C114.2@1092.66,2256.46 C114.2@1093.37,2257.17 ; U13.7@1104.84,1947.7 1110.83,1947.7 1115.52,1943.01 1115.52,1931.7 v2(1117.42,1929.8) ; U12.4@1120.37,1393.09 1121.29,1392.17 1121.29,1367.92 1129.16,1360.05 1133.33,1360.05 1133.66,1359.72 1137.83,1359.72 1140.1,1357.45 C69.2@1140.1,1356.55 ; 1190.37,2256.46 1198.3,2248.53 1206.78,2248.53 ; C123.2@1350.65,1914.81 1356.29,1914.81 v2(1358.55,1912.55) 1359.33,1913.33 v2@1359.33,1913.72
  Top Layer w10: C153.2@268.93,2191.75 C151.2@297.38,2191.75 ; C98.2@290.58,1883.22 291.19,1883.83 307.99,1883.83 317.29,1893.13 317.29,1893.72 320.07,1896.5 R88.1@320.66,1896.5 ; R88.1@320.17,1895.61 321.15,1895.61 327.4,1901.86 335.43,1901.86 341.69,1908.11 v2(344.39,1908.11) ; C72.2@751.98,1306.54 752.18,1306.34 v2(752.18,1298.16) ; C68.2@822.34,1351.76 C68.2@822.34,1352.38
  Top Layer w12: C114.2@1092.66,2256.46 1190.37,2256.46
  Bottom Layer w6: v2(27.15,2210.1) 28.79,2210.1 51.33,2187.56 60.32,2187.56 U18.42@61.69,2186.18 ; U18.57@194.13,2084.26 v2(244.52,2033.87) 296.49,1981.9 U18.15@296.49,1953.35 296.49,1944.5 U18.15@297.43,1943.56 ; U18.19@233.5,1961.35 233.5,1992.93 238.34,1997.77 U18.57@244.52,1997.77 ; C92.2@320.42,1908.4 321.74,1909.72 v2@343.7,1909.72
  Bottom Layer w8: v2@78.07,1322.89 78.23,1323.06 78.23,1408.56 R79.1@78.4,1408.72 ; v2(170.99,1332.45) 172.29,1333.75 172.29,1384.79 R75.1@173.59,1386.09 ; v2(285.83,1723.46) 289.07,1723.46 296.61,1731 320.17,1731 U1.4@320.42,1731.25 343.59,1731.25 355.56,1743.21 356.34,1743.21 364.38,1751.25 C49.2@364.38,1752.04 ; R80.1@459.38,1385.28 459.78,1385.68 R76.1@499.49,1385.68 ; v2@490.05,1896.23 494.7,1891.59 C93.2@514.6,1891.59 R49.1@541,1891.59 ; v2(498.64,1352.72) 499.27,1353.35 499.27,1385.46 R76.1@499.49,1385.68 ; R76.1@499.89,1386.09 R76.1@499.49,1385.68 ; U2.4@647.07,1730.46 663.99,1730.46 C50.2@677.41,1743.87 706.89,1743.87 715.27,1752.25 715.27,1771.26 v2(717.56,1773.56) ; v2(686.6,2205.9) 686.6,2207.76 713.84,2235 C106.2@714.63,2235 ; R77.1@741.3,1444.3 744.29,1441.31 744.29,1428.99 745.02,1428.25 745.02,1422.69 754.6,1413.11 754.6,1394.85 R81.1@754.29,1394.54 754.21,1394.45 754.21,1300.19 v2(752.18,1298.16) ; U3.4@962.68,1730.39 979.61,1730.39 C51.2@993.02,1743.8 1016.98,1743.8 1040.22,1767.04 v2(1063.18,1767.04) ; v2@1002.98,716.59 v2(1003.95,715.62) 1039.01,715.62 U16.4@1040.9,713.73 U16.3@1066.49,713.73 U16.2@1092.08,713.73 U16.7@1092.08,816.09 1094.38,818.39 1094.38,843.14 1105.32,854.08 1105.32,863.05 1109.59,867.32 C83.2@1110.25,867.32 ; v2(1112.89,1317.03) 1112.89,1320.28 1103.37,1329.8 1103.37,1394.2 R82.1@1104.02,1394.85 1133.93,1394.85 1143.25,1385.52 R78.1@1162.12,1385.52 ; C83.2@1116.01,861.57 1117.26,862.82 1117.26,867.32 1117.69,867.75 v1(1143.25,867.75) ; v2(1117.42,1929.8) 1117.42,1933.05 1121.69,1937.32 1121.69,1965.82 1139.44,1983.57 C118.1@1149.32,1983.57 1149.32,2015.45 v2(1171.64,2037.77) 1214.47,2037.77 C119.1@1216.68,2035.56 ; U4.4@1282.98,1730.04 1312.04,1730.04 1321,1739 ; U23.4@1389.51,1816.18 1392.64,1819.31 1417.12,1819.31 v2(1417.8,1820)
  Bottom Layer w10: RT1.1@131.14,1839.39 135.9,1839.39 135.98,1839.46 142.7,1839.46 v2(143.57,1840.33) ; C90.2@140.47,1911.26 C90.2@143.74,1914.53 ; v2@217.94,1893.17 219.85,1891.26 C103.2@219.85,1873.22 ; C103.2@221.25,1871.25 222.03,1871.25 222.03,1841.56 227.89,1835.7 C97.2@248.07,1835.7 ; v2(414.05,1898.67) 435.71,1920.34 435.71,1931.01 438.52,1933.83 C89.2@438.52,1961.35 ; C150.2@426.56,2276.56 426.56,2237.83 432.42,2231.97 NT1.1@451.71,2231.97 ; v1(588.08,1096.92) v1@590.05,1098.9 ; C94.2@656.12,2014.26 656.12,1991.27 644.84,1979.99 644.84,1955.77 653.61,1947.01 656.98,1947.01 658.82,1945.16 U19.2@675.56,1945.16 ; v2(669.83,1909.06) 672.83,1912.06 672.83,1912.59 679.47,1912.59 U19.3@682.35,1915.46 ; U19.2@675.56,1942.29 676.91,1943.64 C96.1@743.85,1943.64 ; R95.1@734.22,2017 R95.1@732.82,2018.4 754.64,2018.4 769.4,2003.65 769.4,1951.12 761.82,1943.53 752.24,1943.53 ; C96.1@743.96,1943.53 752.24,1943.53 ; R92.1@746.32,1887.16 746.32,1922.88 743.83,1925.36 v2(743.83,1928.06) 743.83,1941.67 743.24,1942.26 744.12,1942.39 752.24,1943.53 ; U17.4@1130.64,621.95 U17.3@1130.64,596.36 U17.2@1130.64,570.77 U17.7@1233,570.77 1236.74,567.03 1257.92,567.03 1271.28,553.67 1275.16,553.67 v2(1277.07,551.76) ; GND.1@1317.8,2244.76 GND.1@1317.8,2242.26 1317.8,2169.46 1323.66,2163.6 1331.59,2163.6 1340.43,2154.76 1340.43,2152.53 1340.6,2152.36 1340.6,2144.5 1343.43,2141.67 v2@1344.31,2141.67 ; 1321,1739 1327.24,1745.23 1337.16,1745.23 1344.78,1752.85 1344.78,1762.77 1346.63,1764.63 1346.84,1764.63 C52.2@1348.7,1766.5 1380.02,1766.5 1389.51,1775.99 U23.4@1389.51,1811.18
  other v2: 1271.19,1891.21 217.68,1893.31 489.5,1897.61 136.35,1917.54 143.74,1989.77 244.52,1989.77 195.02,1994.11 1345.18,2021.42 99.64,2033.87 143.74,2033.87 194.13,2033.87 289.94,2042.24 1345.33,2044.73 191.95,2076.49 149.79,2076.88 99.64,2084.26 244.52,2084.26 288.62,2084.26 1345.18,2096.27 1345.18,2120 99.64,2134.65 244.52,2134.65 288.62,2134.65 149.28,2140.44 193.64,2141.61 1345.18,2142.29 143.74,2178.75 194.13,2178.75 244.52,2178.75 1182.79,2195.21 1208.49,2196.34 412.17,2277.56
GPIO35/TDI: TDI.1 U18.36 | length 1556.1
  Top Layer w8: TDI.1@1267.8,2242.26 1267.8,2184.28 1276.28,2175.81 1282.23,2175.81 v2(1284.52,2173.51)
  GND7 w8: v2(25,2118) 38.41,2118 152.81,2232.4 215.34,2232.4 235.38,2252.44 469.06,2252.44 493.24,2276.62 710.06,2276.62 739.25,2247.43 780.26,2247.43 808.05,2275.22 1241.73,2275.22 1284.52,2232.43 v2(1284.52,2173.51)
  Bottom Layer w6: v2(25,2118) 27.68,2115.32 27.68,2111.07 45.78,2092.97 62.39,2092.97 U18.36@63.22,2092.13
GPIO37/TDO: TDO.1 U18.34 | length 1775.7
  Top Layer w8: v2(1252.52,2162.24) 1266.18,2148.57 1291.69,2148.57 1317.8,2174.69 TDO.1@1317.8,2242.26
  GND3/SIG1 w8: v2(22.71,2053.72) 88.39,2053.72 90.53,2055.87 102.36,2055.87 121.64,2075.15 121.64,2079.84 140.68,2098.88 140.9,2098.88 148.28,2106.26 253.64,2106.26 266.62,2093.28 266.62,2034.45 280.83,2020.24 441.07,2020.24 476.72,2055.9 485.21,2055.9 518.19,2088.88 518.19,2197.39 530.89,2210.1 650.98,2210.1 668.78,2227.9 779.52,2227.9 797.97,2209.45 955.72,2209.45 1000.21,2253.94 1223.83,2253.94 1262.52,2215.24 1262.52,2172.92 1252.52,2162.92 v2(1252.52,2162.24)
  Bottom Layer w6: v2(22.71,2053.72) 26.49,2053.72 32.8,2060.03 61.89,2060.03 U18.34@62.86,2061
HB1: C45.1 C53.2 R1.1 U1.8 U5.3 U9.9 | length 645.2
  Top Layer w8: U9.9@138.39,1532.9 139.31,1533.82 139.31,1545.59 141.15,1547.43 141.15,1561.46 153.15,1573.46 153.15,1574.82 160.51,1582.17 160.51,1675.3 130.58,1705.23 v2(130.58,1739.15) 133.34,1739.15 150.89,1756.7 150.89,1764.12 157.98,1771.21 178.05,1771.21 C53.2@179.82,1772.98 184.09,1768.71 U5.3@212.99,1768.71 236.29,1768.69 245.75,1759.23 264.72,1759.23 281.34,1775.85 307.42,1775.85 327.58,1796.01 327.58,1836.3 315.97,1847.91 311.78,1847.91 R1.1@307.51,1852.18
  Bottom Layer w8: v2(130.58,1739.15) 130.58,1741.6 147.74,1758.76 147.74,1763.11 153.54,1768.91 178.18,1768.91 C45.1@179.69,1770.42 ; C45.1@178.03,1768.77 182.78,1773.52 182.78,1785.62 187.47,1790.31 U1.8@210.19,1790.31
HB2: C46.1 C54.2 R2.1 U2.8 U6.3 U10.9 | length 748.4
  Top Layer w8: U10.9@465.45,1533.99 466.37,1534.91 466.37,1565.18 478.86,1577.67 478.86,1747.63 477.82,1748.67 ; v2(506.96,1770.7) 506.96,1773.98 C54.2@506.88,1774.07 504.91,1774.07 493.29,1762.45 493.22,1762.45 478.63,1747.86 471.44,1755.05 432.97,1755.05 423.05,1764.97 423.05,1786.16 426.31,1789.42 426.31,1865.53 480.39,1919.61 498.61,1919.61 506.95,1911.27 509.26,1908.96 587.87,1908.96 630.41,1866.42 630.41,1857.42 R2.1@634.56,1853.27 ; C54.2@511.14,1769.8 U6.3@540.05,1769.8
  Bottom Layer w8: C46.1@513.02,1778.57 523.97,1789.52 U2.8@536.83,1789.52
HB3: C47.1 C55.2 R3.1 U3.8 U7.3 U11.9 | length 596.8
  Top Layer w8: U11.9@783.85,1540.9 783.85,1545.65 785.69,1547.49 785.69,1550.63 798.32,1563.25 v2@798.32,1761.01 ; v2(800.95,1767.94) 800.95,1765.24 797.52,1761.81 800.49,1761.81 809.24,1770.56 821.33,1770.56 C55.2@824.05,1773.28 ; C55.2@824.36,1773.11 828.62,1768.84 U7.3@857.53,1768.84 ; v2(935.24,1880.35) 935.24,1877.42 947.12,1865.55 947.12,1856.58 951.38,1852.31 R3.1@952.05,1852.31
  GND3/SIG4 w8: v2(800.95,1767.94) 844.74,1767.94 935.24,1858.45 v2(935.24,1880.35)
  Bottom Layer w8: v2(800.95,1767.94) 801.76,1768.75 821.14,1768.75 825.52,1773.14 825.52,1785.87 829.1,1789.45 U3.8@852.45,1789.45
HB4: C48.1 C56.2 R4.1 U4.8 U8.3 U12.9 | length 583.1
  Top Layer w8: U12.9@1100.29,1533.72 1100.77,1534.2 1100.77,1551.75 1124.11,1575.08 1124.11,1715.29 1117.32,1722.07 1117.32,1756.05 v2(1116.18,1757.2) 1116.18,1757.58 1119.8,1757.58 1126.55,1764.32 1131.59,1764.32 1136.27,1769.01 1136.27,1769.52 1140.15,1773.39 C56.2@1142.12,1773.39 1143.38,1772.13 U8.3@1175.29,1772.13 ; U8.3@1175.52,1771.89 1203.23,1771.89 1209.44,1765.68 1259.18,1765.68 1290.02,1796.52 1290.02,1847.91 1285.33,1852.6 R4.1@1269.8,1852.6
  Bottom Layer w8: v2(1116.18,1757.2) 1119.42,1757.2 1126.51,1764.29 1137.98,1764.29 1142.24,1768.55 C48.1@1142.24,1769.21 1146.19,1773.16 1146.19,1783.57 1151.72,1789.1 U4.8@1172.74,1789.1
HO1: R17.2 U1.6 U5.2 | length 197.1
  Top Layer w8: R17.2@131.29,1786.44 132.08,1786.44 139.26,1793.61 192.72,1793.61 197.01,1789.32 212.07,1789.32 U5.2@212.99,1788.4 ; U5.2@213.28,1788.11 250.41,1788.11 254.13,1784.38 v2@258.38,1784.38
  Bottom Layer w8: U1.6@210.19,1750.94 211.11,1751.86 229.62,1751.86 255.09,1777.32 255.09,1782.61 v2@256.86,1784.38
  other v2: 257.38,1784.38
HO2: R18.2 U2.6 U6.2 | length 178.4
  Top Layer w8: R18.2@472.69,1778.17 473.48,1778.17 491.25,1795.94 518.76,1795.94 524.29,1790.41 539.13,1790.41 U6.2@540.05,1789.49 ; U6.2@540.16,1789.37 561.55,1789.37 578.65,1772.27 v2(578.65,1764.63)
  Bottom Layer w8: U2.6@536.83,1750.15 537.55,1750.87 552.66,1750.87 557.53,1755.74 569.76,1755.74 v2(578.65,1764.63)
HO3: R19.2 U3.6 U7.2 | length 151.8
  Top Layer w8: R19.2@824.96,1798.01 829.23,1793.74 837.12,1793.74 841.42,1789.45 856.61,1789.45 U7.2@857.53,1788.53 v2(903.79,1788.49)
  Bottom Layer w8: U3.6@852.45,1750.08 853.37,1751 869.4,1751 903.79,1785.39 v2(903.79,1788.49)
HO4: R20.2 U4.6 U8.2 | length 146.2
  Top Layer w8: R20.2@1143.51,1798.3 1147.02,1794.78 1157.49,1794.78 1157.69,1794.58 1160.82,1794.58 1162.66,1792.74 1174.37,1792.74 U8.2@1175.29,1791.81 ; U8.2@1174.37,1790.89 1188.1,1790.89 1189.26,1789.74 1216.5,1789.74 v2(1218.55,1787.68)
  Bottom Layer w8: U4.6@1172.74,1749.73 1173.66,1750.65 1183.4,1750.65 1185.24,1752.49 1191.31,1752.49 1214.97,1776.15 1214.97,1780.85 1218.55,1784.43 v2(1218.55,1787.68)
HS1: C45.2 C53.1 R5.1 R71.1 U1.5 U5.4 U9.8 | length 559
  Top Layer w8: v2(151.58,1501.9) 151.58,1505.15 158.08,1511.64 U9.8@158.08,1532.9 ; v2(165.16,1820.87) 189.56,1820.87 204.61,1835.91 204.61,1842.52 214.27,1852.18 R5.1@215.06,1852.18 ; C53.1@185.99,1749.03 U5.4@212.99,1749.03
  SIG2 w8: v2(151.58,1501.9) 151.58,1505.15 146.53,1510.21 146.53,1701.36 168.58,1723.41 168.58,1731.61 v2(179.79,1742.83)
  GND3/SIG4 w8: v2(165.16,1820.87) 165.16,1819.02 179.79,1804.39 v2(179.79,1742.83)
  Bottom Layer w8: R71.1@153.95,1708.76 153.95,1735.27 161.51,1742.83 v2(179.79,1742.83) 180.51,1742.83 191.16,1732.17 209.26,1732.17 U1.5@210.19,1731.25
HS2: C46.2 C54.1 R6.1 R72.1 U2.5 U6.4 U10.8 | length 446.3
  Top Layer w8: U10.8@485.13,1533.99 485.13,1564.14 492.86,1571.87 492.86,1728.03 501.04,1736.2 501.04,1738.7 504.46,1742.13 v2(506.96,1742.13) ; C54.1@506.88,1742.57 508.85,1742.57 516.39,1750.12 U6.4@540.05,1750.12 ; v2(527.76,1841.86) 529.92,1841.86 539.26,1851.2 R6.1@541.04,1851.2
  SIG2 w8: v2(506.96,1742.13) 509.95,1742.13 528.96,1761.14 528.96,1840.66 v2(527.76,1841.86)
  Bottom Layer w8: v2(506.96,1742.13) 507.07,1742.13 510.6,1738.59 510.6,1738.49 518.63,1730.46 U2.5@536.83,1730.46 536.83,1707 R72.1@533.34,1703.51
HS3: C47.2 C55.1 R7.1 R73.1 U3.5 U7.4 U11.8 | length 543.4
  Top Layer w8: U11.8@802.61,1533.03 803.53,1533.95 803.53,1542.81 814.21,1553.49 814.21,1733.91 824.05,1743.75 C55.1@824.05,1745.2 ; C55.1@826.02,1741.78 833.39,1749.16 U7.4@857.53,1749.16 ; v2(833.12,1898.46) 835.01,1896.57 835.01,1876.46 859.16,1852.31 R7.1@859.6,1852.31
  SIG2 w8: v2@820.42,1744.22 821.78,1745.58 821.78,1802.87 834.69,1815.78 834.69,1896.89 v2(833.12,1898.46)
  Bottom Layer w8: C47.2@820.42,1740.98 821.95,1742.5 821.95,1742.79 833.43,1731.31 851.52,1731.31 U3.5@852.45,1730.39 852.45,1712.53 R73.1@862.14,1702.84
  other v2: 820.42,1743.66
HS4: C48.2 C56.1 R8.1 R74.1 U4.5 U8.4 U12.8 | length 497.8
  Top Layer w8: U12.8@1120.37,1542.17 1121.29,1543.1 1121.6,1543.1 1138.92,1560.41 1138.92,1727.47 v2(1140.98,1729.53) 1140.98,1740.76 C56.1@1142.12,1741.9 1144.09,1741.9 1147.96,1745.77 1147.96,1747.74 1152.66,1752.44 U8.4@1175.29,1752.44 ; v2(1164.95,1871.82) 1164.95,1864.21 1175.96,1853.2 R8.1@1178.29,1853.2
  SIG2 w8: v2(1140.98,1729.53) 1140.98,1845.98 1164.95,1869.95 v2(1164.95,1871.82)
  Bottom Layer w8: v2(1140.98,1729.53) 1145.62,1734.18 1161.72,1734.18 1165.85,1730.04 U4.5@1172.74,1730.04 1172.74,1705.41 R74.1@1175.1,1703.05 ; C48.2@1142.24,1734.18 C48.2@1142.24,1743.23
IPh1: C89.1 R37.2 U18.12 | length 158.8
  Bottom Layer w6: U18.12@317.01,2013.48 382.38,2013.48 411.52,1984.34 411.52,1961.77 C89.1@412.73,1960.56 412.73,1938.24 R37.2@416.68,1934.28
IPh2: C90.1 R38.2 U18.22 | length 72.1
  Bottom Layer w6: R38.2@168.15,1889.41 171.35,1892.6 171.35,1913.69 170.51,1914.53 175.78,1919.79 175.78,1925 186.26,1935.48 U18.22@186.26,1953.35
IPh3: C91.1 R39.2 U18.11 | length 231.5
  Bottom Layer w6: U18.11@335.8,2029.2 337.08,2029.2 337.36,2029.49 392.73,2029.49 434.85,1987.37
  Bottom Layer w8: 434.85,1987.37 442.71,1987.37 451.25,1978.83 451.91,1978.83 465.75,1964.99 C91.1@465.75,1932.59 ; R39.2@454.55,1895.1 458.82,1899.36 R39.2@458.82,1900.15 463.09,1904.42 463.09,1908.02 464.96,1909.89 464.96,1928.32 466.11,1929.47 C91.1@466.11,1932.59
IPh4: C92.1 R40.2 U18.17 | length 88.5
  Bottom Layer w6: U18.17@265,1949.47 265.93,1948.53 265.93,1934.61 286.88,1913.66 289.17,1913.66 295.72,1907.11 295.72,1894.64 301.74,1888.62 301.74,1883.9 R40.2@306.25,1879.39
Ishare: C97.1 R93.1 U18.18 | length 118.5
  Bottom Layer w6: 249.18,1924.26 U18.18@249.18,1942.59
  Bottom Layer w8: 249.18,1924.26 269.48,1903.96 275.59,1897.85 275.59,1864.44 275.59,1837.24 C97.1@274.05,1835.7
Ishare_RS+: J8.1 R45.1 R91.1 R92.2 R93.2 U19.5 | length 3772.1
  SIG3 w8: v2(713.75,1917.93) 713.75,1935.3 728.52,1950.06 901.04,1950.06 1036.07,1815.03 1036.07,1748.4 1059.62,1724.85 1059.62,1405.72 1069.67,1395.67 1134.87,1395.67 1178.03,1352.51 1178.03,1081.32 1068.12,971.41 1068.12,837.95 1174.16,731.91 1174.16,288.49 1131.67,246 985.6,246 960.83,221.23 960.83,195.71 961.08,195.46 931.07,165.44 931.07,76.23 J8.1@960.38,46.91
  GND3/SIG4 w8: v2(247.34,1892.64) 268.87,1892.64 282.43,1906.2 282.43,1947.49 337.95,2003.01 400.99,2003.01 441.17,1962.83 441.17,1832.36 454.17,1819.35 538.64,1819.35 578.97,1859.68 655.5,1859.68 v2(713.75,1917.93)
  Bottom Layer w8: R93.2@247.34,1862.4 247.99,1863.05 247.99,1891.99 v2(247.34,1892.64) ; U19.5@588.94,1942.29 617.08,1942.29 621.77,1937.6 621.77,1908.12 614.24,1900.59 R91.1@614.24,1879.26 614.99,1880.01 708.84,1880.01 715.99,1887.16 R92.2@716.78,1887.16 ; R92.2@713.75,1887.16 v2(713.75,1917.93) ; R45.1@760.99,104.69 761.78,104.69 766.05,100.43 766.05,99.64 781.18,84.51 923.52,84.51 938.79,69.23 938.79,68.51 959.65,47.64 J8.1@960.38,47.64
MCU_TCK: TCK.1 U18.33 | length 1879
  GND7 w8: v2(23.33,2022.91) 23.53,2022.71 48.65,2022.71 71.69,2045.75 71.69,2090.35 91.55,2110.21 193.13,2110.21 202.53,2119.61 202.75,2119.61 218.29,2135.15 218.29,2191.93 258.76,2232.4 504.85,2232.4 520.17,2217.07 650.06,2217.07 661.88,2228.89 840.05,2228.89 857.5,2211.44 962.82,2211.44 976.56,2225.18 976.56,2233.12 995.21,2251.77 1124.78,2251.77 1160.79,2215.76 1160.79,2142.06 1182.85,2120 1240.66,2120 1271.25,2150.59 1305.03,2150.59 1313.95,2159.51 1313.95,2192.43 1329.23,2207.71 1393.04,2207.71 v2(1425.55,2175.21)
  Bottom Layer w6: v2(23.33,2022.91) 45.13,2044.71 63.05,2044.71 U18.33@63.22,2044.89
  Bottom Layer w8: TCK.1@1417.8,2244.76 TCK.1@1417.8,2242.26 1417.8,2183.89 1425.55,2176.15 v2(1425.55,2175.21) v2@1425.55,2173.21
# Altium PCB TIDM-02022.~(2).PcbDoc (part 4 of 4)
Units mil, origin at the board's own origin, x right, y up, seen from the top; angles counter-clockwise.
Board outline 1448.82 x 2299.21 mil, 16 copper layers (Top Layer, GND1, PWR1, PWR2, PWR3, GND2, GND3/SIG1, SIG2, SIG3, GND3/SIG4, GND5, PWR4, PWR5, GND6, GND7, Bottom Layer), stack 148.806 mil thick; 257 components, 138 nets, 739 pads, 1147 vias.

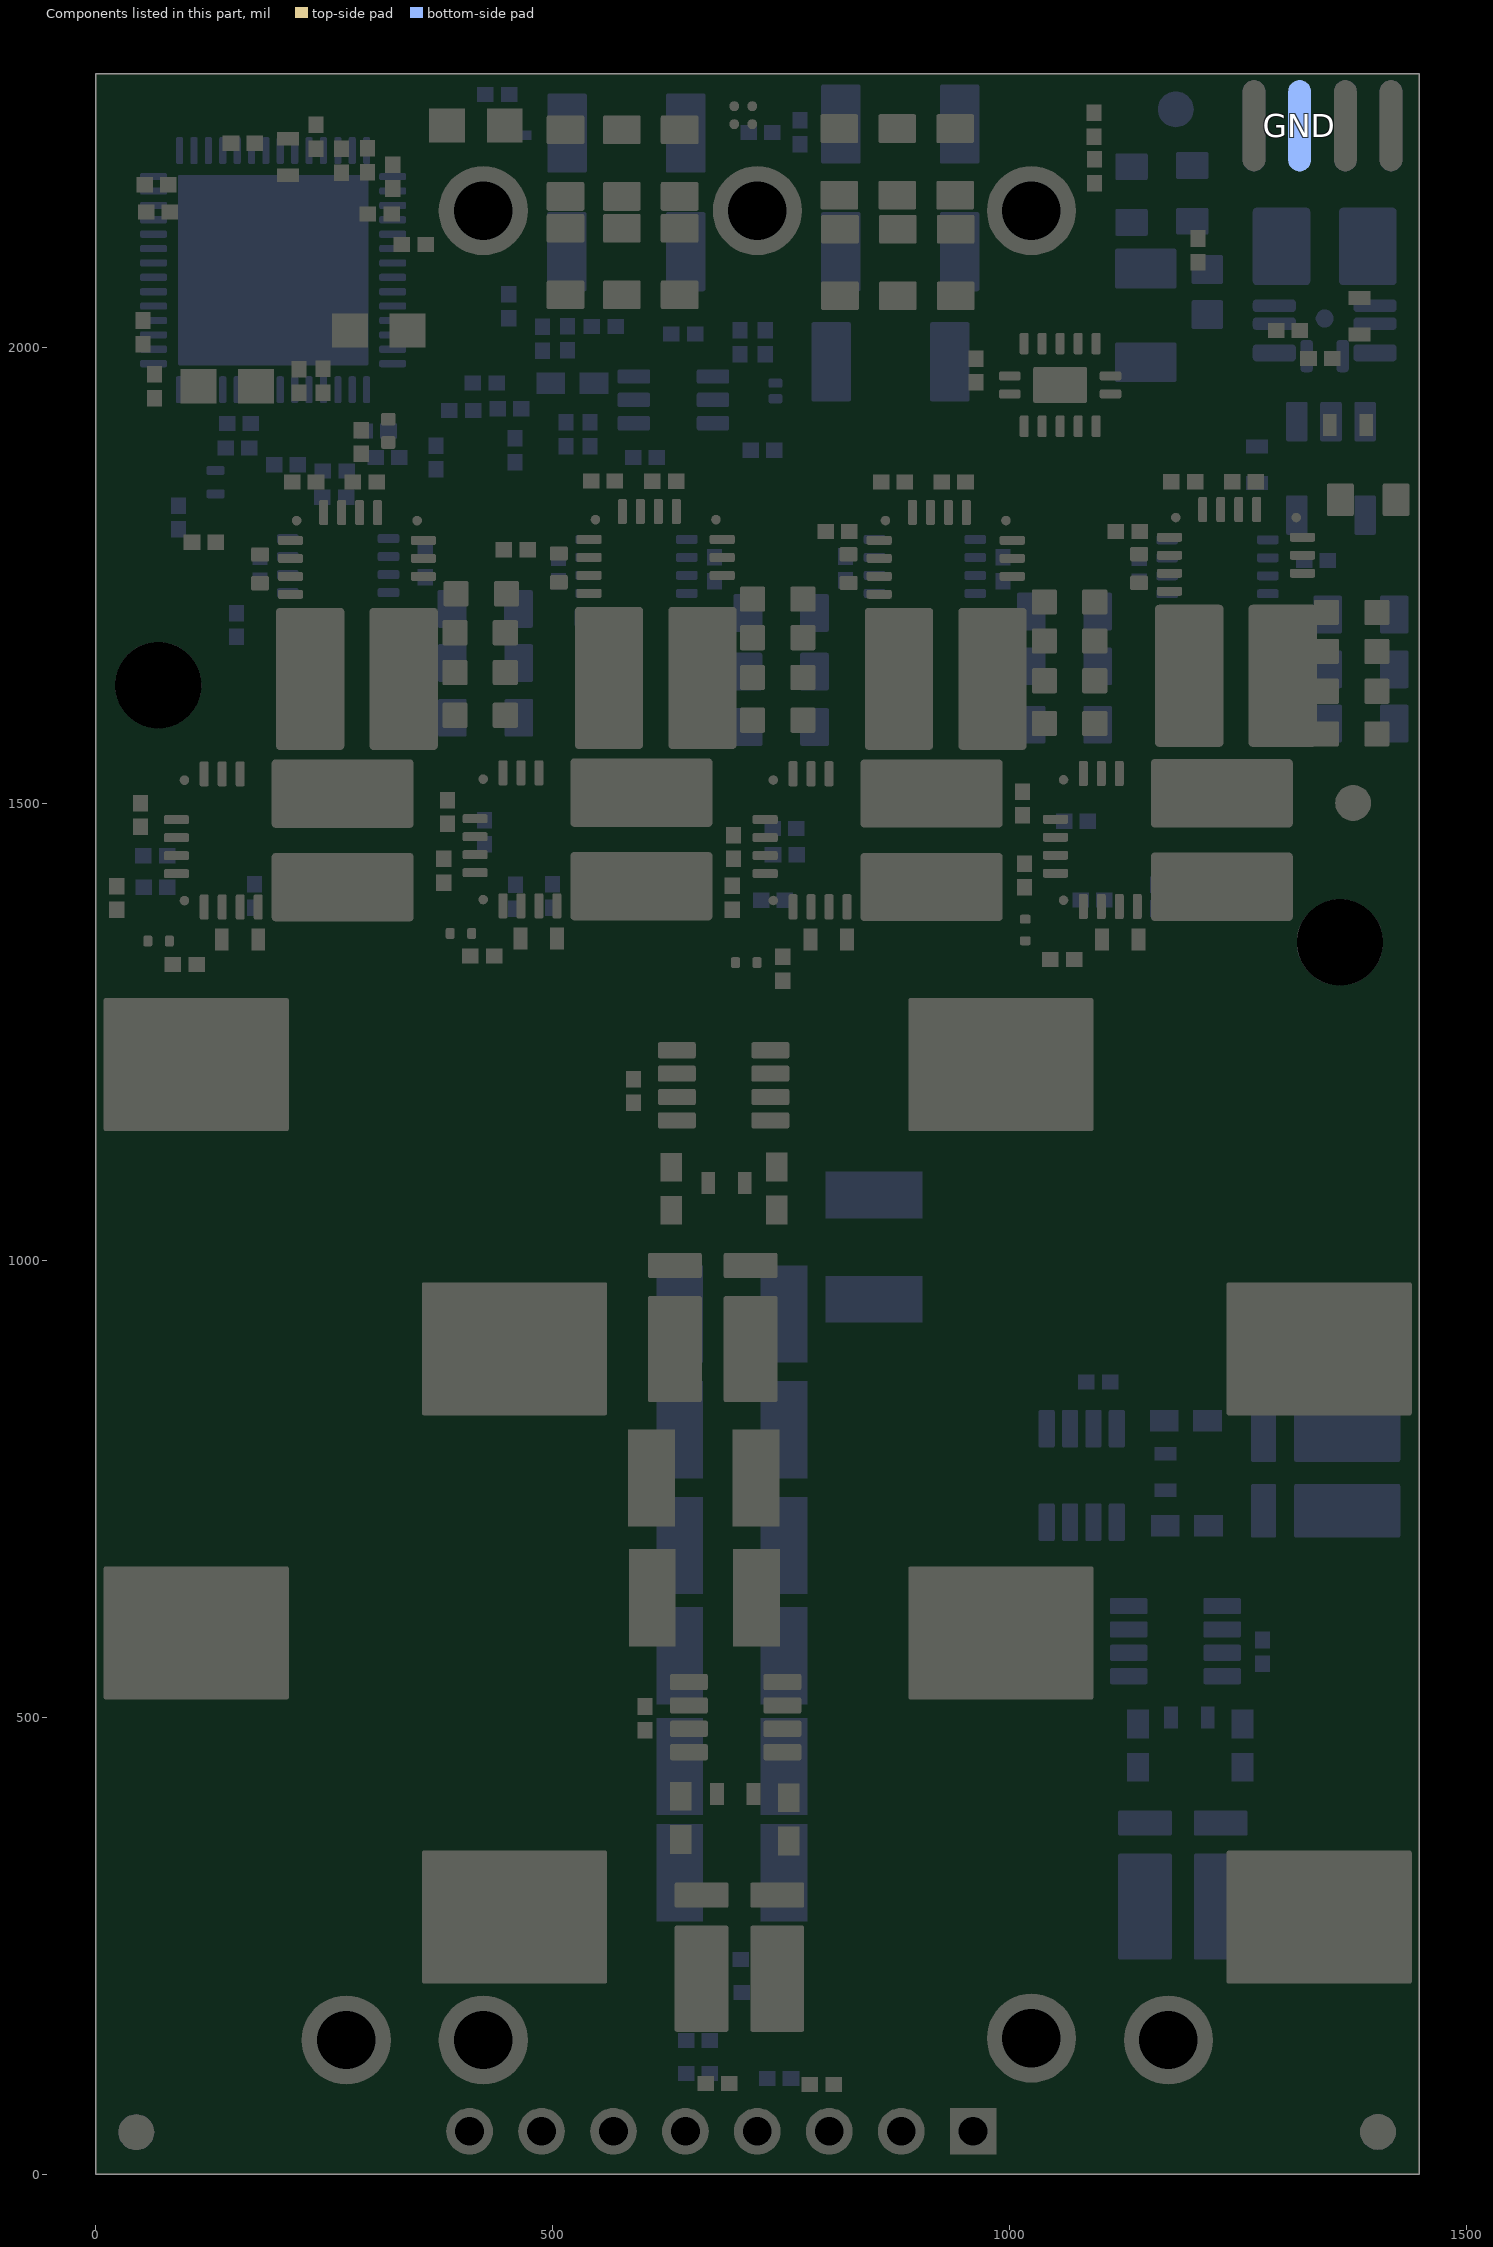
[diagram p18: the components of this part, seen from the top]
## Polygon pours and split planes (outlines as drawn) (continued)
VOUT3 on Top Layer "TOP_LAYER_VOUT3_P048" (solid, remove dead copper, pour order 48): 1162.12,994.94 1444.63,994.94 1444.63,827.62 1162.12,827.62
VOUT1 on Top Layer "TOP_LAYER_VOUT1_P139" (solid, remove dead copper, pour order 139): 663.33,963.85 613.57,963.85 594.24,983.17 367.51,983.17 358.03,973.69 358.03,828.58 364.53,822.08 650.04,822.08 663.33,835.37
SW4 on Top Layer "NONET_L-01_P-001" (solid, remove dead copper, pour order 229): 1328.74,1474.06 1317.83,1463.15 1161.43,1463.15 1152.12,1472.46 1152.12,1712.46 1160.68,1721.02 1233.71,1721.02 1247.53,1707.19 1247.53,1556.99 1255.46,1549.06 1260.77,1549.06 1306.22,1549.06 1328.74,1526.54
SW3 on Top Layer "NONET_L-01_P-001" (solid, remove dead copper, pour order 220): 830.91,1551.75 825.64,1546.47 825.64,1470.42 829.52,1466.54 994.1,1466.54 994.1,1545.28 935.04,1545.28 925.2,1555.12 925.2,1712.6 922.5,1715.29 840.78,1715.29 830.91,1705.43
VIN on Top Layer "TOP_LAYER_VIN_P173" (solid, remove dead copper, pour order 173): 944.88,1712.6 964.57,1732.28 1043.31,1732.28 1053.15,1722.44 1053.15,1564.96 1043.31,1555.12 944.88,1555.12
VIN on Top Layer "TOP_LAYER_VIN_P172" (solid, remove dead copper, pour order 172): 1259.84,1555.12 1368.11,1555.12 1368.11,1722.44 1358.27,1732.28 1259.84,1732.28
PGND on Top Layer "TOP_LAYER_PGND_P153" (solid, remove dead copper, pour order 153): 1383.19,1560.54 1409.74,1533.99 1430.49,1533.99 1436.63,1540.12 1436.63,1718.88 1427.56,1727.95 1427.47,1727.86 1383.19,1727.86
PGND on Top Layer "TOP_LAYER_PGND_P146" (solid, remove dead copper, pour order 146): 748.03,1580.58 748.03,1747.9 777.56,1747.9 787.4,1738.06 787.4,1580.58
SW1 on Top Layer "TOP_LAYER_SW1_P144" (solid, remove dead copper, pour order 144): 272.75,1715.44 195.02,1715.44 182.11,1702.52 182.11,1477.45 185.48,1474.08 208.99,1474.08 216.54,1466.54 344.49,1466.54 344.49,1545.28 334.65,1555.12 285.43,1555.12 285.43,1702.76
VOUT4 on Top Layer "TOP_LAYER_VOUT4_P105" (solid, remove dead copper, pour order 105): 1240.16,206.69 1220.47,226.38 1220.47,374.02 1259.84,413.39 1437.01,413.39 1437.01,206.69
VOUT4 on Top Layer "TOP_LAYER_VOUT4_P061" (solid, remove dead copper, pour order 61): 1240.16,206.69 1220.47,226.38 1220.47,374.02 1250.68,404.22 1437.01,404.22 1437.01,206.69
VOUT4 on Top Layer "TOP_LAYER_VOUT4_P060" (solid, remove dead copper, pour order 60): 1240.16,206.69 1220.47,226.38 1220.47,374.02 1259.84,413.39 1437.01,413.39 1437.01,206.69
VIN on PWR3 "PWR3_VIN_P047" (solid, remove dead copper, pour order 47): 37 vertices, not listed, extent 295.28,1564.96 1437.01,2283.46
GND on PWR3 "NONET_L-01_P-001" (solid, remove dead copper, pour order 339): 17 vertices, not listed, extent 16.81,1716.91 422.8,2286.6
SW4 on PWR3 "PWR3_SW4_P016" (solid, remove dead copper, pour order 16): 24 vertices, not listed, extent 884.08,509 1435.26,1693.58
SW2 on PWR3 "PWR3_SW2_P207" (solid, remove dead copper, pour order 207): 29 vertices, not listed, extent 8.1,490.83 697.07,1691.39
SW1 on PWR3 "PWR3_SW1_P201" (solid, remove dead copper, pour order 201): 17 vertices, not listed, extent 9.67,1136.16 346.82,1701.69
VOUT on PWR3 "PWR3_VOUT_P199" (solid, remove dead copper, pour order 199): 678.01,984.25 678.01,118.11 712.16,83.96 997.6,83.96 1002.81,78.74 1002.81,19.68 1012.65,9.84 1406.36,9.84 1435.88,39.37 1435.88,767.72 1130.76,767.72 914.23,984.25
VDDIO_3V3 on PWR3 "NONET_L-01_P-001" (solid, remove dead copper, pour order 275): 19 vertices, not listed, extent 11.12,2132.22 301.87,2283.99
SW3 on PWR3 "PWR3_SW3_P213" (solid, remove dead copper, pour order 213): 20 vertices, not listed, extent 713.75,1114.43 1092.34,1694.16
VOUT2 on PWR3 "PWR3_VOUT2_P102" (solid, remove dead copper, pour order 102): 357.17,352.91 361.84,357.58 624.97,357.58 624.97,200.81 365.2,200.81 357.17,208.85
PGND on PWR3 "NONET_L-01_P-001" (solid, remove dead copper, pour order 200): 19.69,442.91 49.21,472.44 324.8,472.44 344.49,452.76 344.49,206.69 354.33,196.85 616.99,196.85 630.66,183.17 630.59,183.1 630.59,84.86 571.7,25.97 72.46,25.97 19.69,78.74
VOUT1 on PWR3 "PWR3_VOUT1_P074" (solid, remove dead copper, pour order 74): 358.03,973.69 367.51,983.17 616.26,983.17 616.26,832.06 620.61,827.71 614.97,822.08 364.53,822.08 358.03,828.58
VOUT4 on PWR3 "PWR3_VOUT4_P092" (solid, remove dead copper, pour order 92): 1240.16,206.69 1220.47,226.38 1220.47,374.02 1259.84,413.39 1437.01,413.39 1437.01,206.69
VOUT3 on PWR3 "PWR3_VOUT3_P053" (solid, remove dead copper, pour order 53): 1230.32,994.75 1229.2,993.63 1174.84,993.63 1163,981.79 1163,845.63 1181.2,827.43 1446.85,827.43 1446.85,994.75
PGND on Top Solder "TOP_LAYER_NONET_P187" (solid, remove dead copper, pour order 187): 196.85,1368.11 196.85,1324.65 232.13,1289.37 344.49,1289.37 344.49,1348.43 324.8,1368.11
PGND on Top Solder "TOP_LAYER_NONET_P188" (solid, remove dead copper, pour order 188): 531.5,1367.67 531.5,1289.37 669.29,1289.37 669.29,1367.67
no net on Top Solder "TOP_LAYER_NONET_P188" (solid, remove dead copper): 1163.21,1367.69 1163.21,1289.39 1276.29,1289.39 1276.29,1367.69
no net on Top Solder "TOP_LAYER_NONET_P188" (solid, remove dead copper): 848.13,1363.18 848.13,1309.06 985.92,1309.06 985.92,1363.18
VIN on PWR2 "PWR2_VIN_P096" (solid, remove dead copper, pour order 96): 43 vertices, not listed, extent 290.53,1565.89 1437.01,2284.4
GND on PWR2 "NONET_L-01_P-001" (solid, remove dead copper, pour order 337): 17 vertices, not listed, extent 11.41,1716.74 428.15,2286.6
SW4 on PWR2 "PWR2_SW4_P091" (solid, remove dead copper, pour order 91): 23 vertices, not listed, extent 885.83,526.7 1437.01,1690.84
SW2 on PWR2 "PWR2_SW2_P217" (solid, remove dead copper, pour order 217): 30 vertices, not listed, extent 8.1,489.08 693.36,1704.75
SW1 on PWR2 "PWR2_SW1_P216" (solid, remove dead copper, pour order 216): 20 vertices, not listed, extent 11.41,1134.41 348.57,1697.72
VOUT on PWR2 "PWR2_VOUT_P089" (solid, remove dead copper, pour order 89): 22 vertices, not listed, extent 678.01,9.84 1435.88,957.27
SW3 on PWR2 "PWR2_SW3_P218" (solid, remove dead copper, pour order 218): 21 vertices, not listed, extent 697.07,1132.05 1092.34,1694.57
VOUT2 on PWR2 "PWR2_VOUT2_P118" (solid, remove dead copper, pour order 118): 357.17,352.91 361.84,357.58 624.97,357.58 624.97,200.81 365.2,200.81 357.17,208.85
PGND on PWR2 "NONET_L-01_P-001" (solid, remove dead copper, pour order 219): 17.94,449.9 47.47,479.43 323.06,479.43 342.74,459.74 342.74,213.68 352.58,203.84 615.24,203.84 628.92,190.16 628.84,190.09 628.84,91.84 568.45,31.45 72.22,31.45 17.94,85.73
VOUT3 on PWR2 "PWR2_VOUT3_P064" (solid, remove dead copper, pour order 64): 1214.5,827.62 1164.95,877.16 1164.95,986.57 1177.62,999.23 1441.71,999.23 1446.01,994.94 1446.01,827.62
VOUT4 on PWR2 "PWR2_VOUT4_P085" (solid, remove dead copper, pour order 85): 1240.16,206.69 1220.47,226.38 1220.47,374.02 1259.84,413.39 1437.01,413.39 1437.01,206.69
VOUT1 on PWR2 "PWR2_VOUT1_P215" (solid, remove dead copper, pour order 215): 358.03,973.69 367.51,983.17 616.26,983.17 616.26,823.36 606.6,813.7 372.9,813.7 358.03,828.58
VIN on PWR4 "PWR4_VIN_P075" (solid, remove dead copper, pour order 75): 40 vertices, not listed, extent 292.72,1565.89 1437.01,2284.4
GND on PWR4 "NONET_L-01_P-001" (solid, remove dead copper, pour order 342): 396.75,2278.53 397.98,2277.3 462.25,2277.3 495.55,2244 495.55,2006.14 287.96,1798.55 287.96,1731.13 266.19,1709.36 42.75,1709.36 13,1739.1 13,2276.33 16.25,2279.58 396.75,2279.58
SW2 on PWR4 "PWR4_SW2_P212" (solid, remove dead copper, pour order 212): 29 vertices, not listed, extent 8.1,494.32 697.07,1697.85
SW4 on PWR4 "PWR4_SW4_P056" (solid, remove dead copper, pour order 56): 25 vertices, not listed, extent 885.83,504.16 1437.01,1690.84
SW1 on PWR4 "PWR4_SW1_P196" (solid, remove dead copper, pour order 196): 17 vertices, not listed, extent 11.41,1134.41 348.57,1704.41
VOUT on PWR4 "PWR4_VOUT_P194" (solid, remove dead copper, pour order 194): 678.01,984.25 710.76,1017 881.48,1017 1130.76,767.72 1435.88,767.72 1435.88,39.37 1406.36,9.84 1012.65,9.84 1002.81,19.68 1002.81,78.74 997.6,83.96 712.16,83.96 678.01,118.11
SW3 on PWR4 "PWR4_SW3_P203" (solid, remove dead copper, pour order 203): 22 vertices, not listed, extent 697.07,1128.84 1092.34,1695.97
VOUT2 on PWR4 "PWR4_VOUT2_P111" (solid, remove dead copper, pour order 111): 357.17,352.91 361.84,357.58 624.97,357.58 624.97,200.81 365.2,200.81 357.17,208.85
VOUT1 on PWR4 "PWR4_VOUT1_P090" (solid, remove dead copper, pour order 90): 358.03,973.69 367.51,983.17 616.26,983.17 616.26,832.06 620.61,827.71 614.97,822.08 364.53,822.08 358.03,828.58
VOUT4 on PWR4 "PWR4_VOUT4_P109" (solid, remove dead copper, pour order 109): 1240.16,206.69 1220.47,226.38 1220.47,374.02 1259.84,413.39 1437.01,413.39 1437.01,206.69
VOUT3 on PWR4 "PWR4_VOUT3_P040" (solid, remove dead copper, pour order 40): 1230.32,828.42 1201.09,828.42 1156.76,872.74 1156.76,983.02 1177.47,1003.73 1438.02,1003.73 1446.01,995.74 1446.85,995.74 1446.85,828.42
PGND on PWR4 "NONET_L-01_P-001" (solid, remove dead copper, pour order 195): 19.69,442.91 49.21,472.44 324.8,472.44 344.49,452.76 344.49,206.69 354.33,196.85 616.99,196.85 630.66,183.17 630.59,183.1 630.59,84.86 574.66,28.92 69.5,28.92 19.69,78.74
VIN on PWR1 "PWR1_VIN_P297" (solid, remove dead copper, pour order 297): 40 vertices, not listed, extent 295.28,1565.89 1437.01,2284.4
GND on PWR1 "NONET_L-01_P-001" (solid, remove dead copper, pour order 336): 395.16,2221.03 380.88,2235.32 380.88,2267.4 371.14,2276.97 18.25,2276.97 14.66,2280.55 11.41,2277.3 11.41,1718.61 245.47,1718.61 247.34,1716.74 279.17,1748.57 279.17,1796.97 395.16,1912.97 395.16,2193.29
SW2 on PWR1 "PWR1_SW2_P306" (solid, remove dead copper, pour order 306): 28 vertices, not listed, extent 8.1,494.32 697.07,1696.36
SW4 on PWR1 "PWR1_SW4_P296" (solid, remove dead copper, pour order 296): 22 vertices, not listed, extent 885.83,526.7 1437.01,1687.88
SW1 on PWR1 "PWR1_SW1_P304" (solid, remove dead copper, pour order 304): 17 vertices, not listed, extent 11.41,1134.41 348.57,1700.87
VOUT on PWR1 "PWR1_VOUT_P302" (solid, remove dead copper, pour order 302): 678.01,984.25 678.01,118.11 712.16,83.96 997.6,83.96 1002.81,78.74 1002.81,19.68 1012.65,9.84 1406.36,9.84 1435.88,39.37 1435.88,767.72 1130.76,767.72 914.23,984.25
VOUT3 on PWR1 "PWR1_VOUT3_P298" (solid, remove dead copper, pour order 298): 1230.32,828.42 1156.94,901.8 1156.94,980.77 1181.17,1005 1435.95,1005 1446.01,995.74 1446.85,995.74 1446.85,828.42
SW3 on PWR1 "PWR1_SW3_P305" (solid, remove dead copper, pour order 305): 25 vertices, not listed, extent 697.07,1127.1 1092.34,1693.21
VOUT1 on PWR1 "PWR1_VOUT1_P299" (solid, remove dead copper, pour order 299): 358.03,973.69 367.51,983.17 616.26,983.17 616.26,832.06 620.61,827.71 614.97,822.08 364.53,822.08 358.03,828.58
PGND on PWR1 "NONET_L-01_P-001" (solid, remove dead copper, pour order 303): 19 vertices, not listed, extent 19.69,16.5 630.66,472.44
VOUT2 on PWR1 "PWR1_VOUT2_P301" (solid, remove dead copper, pour order 301): 357.17,352.91 361.84,357.58 624.97,357.58 624.97,200.81 365.2,200.81 357.17,208.85
VOUT4 on PWR1 "PWR1_VOUT4_P300" (solid, remove dead copper, pour order 300): 1240.16,206.69 1220.47,226.38 1220.47,374.02 1259.84,413.39 1437.01,413.39 1437.01,206.69
PGND on GND5 "GND5_PGND_P084" (solid, remove dead copper, pour order 84): 28 vertices, not listed, extent 9.84,9.84 1439.14,2283.46
GND on GND5 "NONET_L-01_P-001" (solid, remove dead copper, pour order 341): 379.56,2279.58 387.46,2287.49 414.68,2287.49 424.16,2278.01 424.16,2235.31 378.25,2189.39 378.25,2081.22 441.23,2018.23 441.23,1833.34 398.56,1790.66 33.63,1790.66 29.96,1786.99 21.57,1795.38 21.57,2276.33 24.82,2279.58
VOUT3 on GND5 "GND5_VOUT3_P030" (solid, remove dead copper, pour order 30): 1229.47,827.62 1168.09,889 1168.09,983.74 1178.58,994.23 1229.47,994.23 1229.47,994.94 1446.01,994.94 1446.01,827.62
VOUT1 on GND5 "GND5_VOUT1_P058" (solid, remove dead copper, pour order 58): 358.03,973.69 367.51,983.17 600.39,983.17 600.39,822.08 364.53,822.08 358.03,828.58
VOUT on GND5 "GND5_VOUT_P076" (solid, remove dead copper, pour order 76): 19 vertices, not listed, extent 678.01,9.84 1435.88,940.72
VOUT2 on GND5 "GND5_VOUT2_P068" (solid, remove dead copper, pour order 68): 357.17,352.91 361.84,357.58 600.39,357.58 600.39,200.81 365.2,200.81 357.17,208.85
VOUT4 on GND5 "GND5_VOUT4_P066" (solid, remove dead copper, pour order 66): 1240.16,206.69 1220.47,226.38 1220.47,374.02 1259.84,413.39 1437.01,413.39 1437.01,206.69
PGND on GND6 "GND6_PGND_P316" (solid, remove dead copper, pour order 316): 28 vertices, not listed, extent 8.26,11.58 1437.56,2285.21
GND on GND6 "NONET_L-01_P-001" (solid, remove dead copper, pour order 338): 441.71,1952.3 441.71,2016.44 368.22,2089.93 368.22,2185.49 424.03,2241.3 424.03,2272.64 415.14,2281.54 413.18,2279.58 16.25,2279.58 13,2276.33 13,1805.87 367.89,1805.87 367.95,1805.81 402.83,1805.81 441.17,1844.15
VOUT3 on GND6 "GND6_VOUT3_P311" (solid, remove dead copper, pour order 311): 1170.75,996.68 1444.43,996.68 1444.43,829.36 1170.75,829.36
VOUT on GND6 "GND6_VOUT_P315" (solid, remove dead copper, pour order 315): 19 vertices, not listed, extent 676.43,11.58 1434.3,942.46
VOUT2 on GND6 "GND6_VOUT2_P314" (solid, remove dead copper, pour order 314): 355.59,354.65 360.26,359.32 598.81,359.32 598.81,202.55 363.62,202.55 355.59,210.59
VOUT4 on GND6 "GND6_VOUT4_P313" (solid, remove dead copper, pour order 313): 1238.58,208.43 1218.89,228.12 1218.89,375.76 1258.26,415.13 1435.43,415.13 1435.43,208.43
VOUT1 on GND6 "GND6_VOUT1_P312" (solid, remove dead copper, pour order 312): 356.45,975.43 365.93,984.91 598.81,984.91 598.81,823.82 362.95,823.82 356.45,830.32
PGND on GND2 "GND2_PGND_P133" (solid, remove dead copper, pour order 133): 0,1726.44 54.4,1780.85 407.16,1780.85 408.25,1779.76 442.1,1813.6 442.1,2048.31 373.21,2118.72 373.21,2178.06 488.45,2293.31 1446.85,2293.31 1446.85,0 0,0
GND on GND2 "NONET_L-01_P-001" (solid, remove dead copper, pour order 340): 365.94,2278.53 374.38,2286.98 424.12,2286.98 430.83,2280.27 430.83,2250.42 368.75,2188.34 368.75,2080.17 431.73,2017.18 431.73,1832.29 389.06,1789.61 24.13,1789.61 20.46,1785.94 12.07,1794.33 12.07,2275.28 15.32,2278.53
PGND on GND1 "NONET_L-01_P-001" (solid, remove dead copper, pour order 335): 362.95,1866.42 384.67,1888.15 384.67,2228.95 435.25,2279.53 1067.17,2279.53 1069.18,2281.54 1408.25,2281.54 1438.37,2251.42 1438.37,38.28 1409.93,9.84 54.25,9.84 16.09,48 16.09,118.55 18.41,1843.73 41.11,1866.42
GND on GND1 "NONET_L-01_P-001" (solid, remove dead copper, pour order 344): 18.09,1874.16 22.18,1870.08 341.61,1870.08 373.85,1902.32 373.85,2176.16 397.19,2199.49 397.19,2267.97 374.06,2291.1 33.69,2291.1 7.09,2264.5 7.09,2162
GND on GND1 "NONET_L-01_P-001" (solid, remove dead copper, pour order 330): 1000.27,1897.61 1116.9,1897.61 1116.9,1898.17 1134.67,1915.94 1134.67,1992.53 1111.5,2015.69 1003.82,2015.69 975.34,1987.21 975.34,1904.72 983.57,1896.5
GND on GND1 "NONET_L-01_P-001" (solid, remove dead copper, pour order 324): 1255.16,2171.63 1394.64,2171.63 1395.65,2172.63 1408.93,2159.35 1408.93,2156.28 1410.95,2154.25 1410.95,1990.93 1391.57,1971.54 1283.92,1971.54 1247.3,2008.16 1247.3,2163.02 1255.16,2170.88
GND on GND1 "GND1_GND_P331" (solid, remove dead copper, pour order 331): 19 vertices, not listed, extent 570.75,977.96 759.12,1237.34
GND on GND1 "GND1_GND_P333" (solid, remove dead copper, pour order 333): 22 vertices, not listed, extent 572.85,286.3 779.49,545.64
GND on GND7 "GND7-GND" (solid, remove dead copper, pour order 350): 30 vertices, not listed, extent 7.09,1831.12 695.95,2291.1
PGND on GND7 "NONET_L-01_P-001" (solid, remove dead copper, pour order 349): 25 vertices, not listed, extent 15.09,14 1441.09,2288.6
GND on GND7 "NONET_L-01_P-001" (solid, remove dead copper, pour order 346): 1299.21,1833.54 1324.66,1808.09 1421.81,1808.09 1432.85,1819.13 1432.85,2146.27 1416.89,2162.24 1286.16,2162.24 1262.95,2139.03 1262.95,1977.55 1299.21,1941.29
GND on GND7 "NONET_L-01_P-001" (solid, remove dead copper, pour order 348): 38 vertices, not listed, extent 980.54,370.62 1298,883.34
GND on SIG3 "SIG3_GND_P318" (solid, remove dead copper, pour order 318): 1.23,2.93 1.23,2296.24 1448.08,2296.24 1448.08,2.93
GND on GND3/SIG1 "GND3/SIG1_GND_P351" (solid, remove dead copper, pour order 351): 0,2.99 0,2296.29 1446.85,2296.29 1446.85,2.99
5V on GND3/SIG1 "NONET_L-01_P-001" (solid, pour order 274): 1269.69,2128.31 1270.8,2129.42 1314.45,2129.42 1318.17,2125.7 1318.17,2085.48 1303.1,2070.41 1273.13,2070.41 1263.85,2079.7 1263.85,2122.68 1269.47,2128.31
GND on GND3/SIG4 "GND3/SIG4_GND_P319" (solid, remove dead copper, pour order 319): -0.27,1.83 -0.27,2295.14 1446.59,2295.14 1446.59,1.83
GND on SIG2 "SIG2_GND_P320" (solid, remove dead copper, pour order 320): 0.23,2.04 0.23,2295.35 1447.08,2295.35 1447.08,2.04

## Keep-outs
Keep-Out Layer:
  text ".Layer_Name" at 577,-858.49 h60

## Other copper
Top Layer:
  rectangle net HB2: 472.44,1751.51 482.28,1756.79
  text ".Layer_Name" at 577,-858.49 h60
SIG3:
  text ".Layer_Name" at 805.09,-853 h50
PWR2:
  text ".Layer_Name" at 724.61,-865 h50
GND1:
  text ".Layer_Name" at 676.71,-865 h50
PWR3:
  text ".Layer_Name" at 757.09,-853 h50
PWR4:
  text ".Layer_Name" at 836.29,-853 h50
GND7:
  text ".Layer_Name" at 781.09,-861 h50
PWR5:
  text ".Layer_Name" at 853.09,-841 h50
SIG2:
  text ".Layer_Name" at 773.09,-849 h50
GND5:
  text ".Layer_Name" at 653.09,-861 h50
GND3/SIG4:
  text ".Layer_Name" at 713.09,-865 h50
GND3/SIG1:
  text ".Layer_Name" at 681.01,-853 h50
GND2:
  text ".Layer_Name" at 724.22,-845 h50
GND6:
  text ".Layer_Name" at 829.09,-841 h50
PWR1:
  text ".Layer_Name" at 681.01,-865 h50
Bottom Layer:
  region net GND: 1351.96,1977.48 1351.91,1977.43 1351.91,1974.84 1346.93,1969.86 1344.58,1969.88 1325,1969.88 1320.9,1974.2 1320.9,2009.03 1330.43,2018.56 1330.43,2019.32 1330.71,2019.6 1330.71,2052.25 1337.13,2058.67 1337.13,2150.34 1340.35,2153.56 1349.45,2153.56 1353.32,2149.68 1353.32,2068.83 1353.29,2068.8 1354.81,2067.28 1354.81,2019.1 1351.96,2016.25
  pour cut-out: 1379,1972 1379,1951.66 1389.07,1941.59 1412.34,1941.59 1421.17,1950.43 1432.09,1950.43 1432.09,1962.3 1420.62,1973.76 1420.62,1974.78 1381.15,1974.78 1378.98,1972.61 1378.98,1972.16
  pour cut-out: 1133.09,1481 1149.26,1481 1150.51,1479.75 1150.51,1466.76 1134.87,1466.76 1134.65,1466.54 1132.07,1469.11 1132.07,1476.38
  pour cut-out: 474,2239 478.24,2239 479.4,2237.84 479.4,2225.69 478.53,2224.81 474.18,2224.81 471.46,2227.54 471.46,2238.29 472.21,2239.05
  text ".Layer_Name" at 577,-858.49 h60

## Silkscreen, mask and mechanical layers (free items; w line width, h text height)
Top Overlay:
  circle w10: c723.53,2214.77 r3.38
  circle w10: c1367,148.59 r27.9
  circle w10: c851.52,1186.95 r27.52
  circle w10: c143.42,143.68 r26.02
  circle w10: c484.64,1294.51 r26.02
  lines w6: 12.02,92 12.02,186 ; 34,202 155.56,200.26 187,170.74 187,149.1 220,116.1 220,66 180,26 90.09,28 ; 205.61,2009.79 208.28,2009.79 220.98,1997.09 220.98,1994.45 ; 224.89,2039 136.56,2039 105.61,2069.95 105.61,2172.61 136,2203 184.63,2203 191,2209.37 191,2255 215.48,2279.48 278.94,2279.48 ; 247.92,2055.81 281.01,2055.81 293.55,2068.35 293.55,2112.08 309.47,2128 336.23,2128 344.68,2136.45 344.68,2213.75 ; 280.32,2278.53 280.62,2278.53 296.26,2262.89 296.26,2251.72 323.57,2224.41 332.96,2224.41 343.62,2213.75 ; 383.47,1530.28 368.44,1530.28 356.89,1518.73 356.89,1343.01 384.88,1315.02 450.08,1315.02 465.5,1330.44 513.48,1330.44 521.97,1338.93 521.97,1363 ; 391.05,1777 401.21,1766.84 401.21,1766.39 ; 406,1902 405.65,1902 401.21,1897.56 401.21,1766.39 ; 410.33,1776.39 401.21,1767.27 401.21,1766.39 ; 582.82,287 582.82,319.82 605.15,342.15 606.61,342.15 ; 594.91,451 599.97,456.06 599.97,466.27 ; 677.46,1285.57 683.75,1291.87 683.75,1298.16 ; 683.77,1300.09 684.24,1361.35 ; 727.81,1850.55 738.55,1861.29 738.78,1861.29 738.78,1860.99 748.43,1851.34 ; 738.78,1776.92 738.78,1860.24 ; 766.19,1298.16 772.9,1293.21 ; 852.61,1225 852.61,1266.1 884.67,1298.16 1002.63,1298.16 1009.5,1305.03 1010.33,1305.03 ; 995.57,1348.43 997.03,1346.97 997.03,1321.49 998.67,1319.85 ; 996.57,1321.95 1011.51,1307.01 1106.36,1307.01 1116.38,1317.03 1143.25,1317.03 ; 996.57,1462.86 996.57,1527.12 ; 1002.46,1531.39 1028.46,1531.39 ; 1067.26,1763.77 1067.19,1780.72 1066.93,1850.83 1127.68,1905.62 1226.21,1905.62 ; 1244.49,2183.82 1299.76,2183.82 ; 1252,194 1230,172 1230,40.33 1256.33,14 1346.09,14 ; 1254,194 1395.84,194 1435,154.83 1435,102.91 ; 1274.1,2037.77 1273.71,1993.66 1291.43,1980.55 1289.82,1923.08 1289.9,1883.48 1306.71,1860.99 1327.23,1860.99 ; 1328.41,1860.68 1336.11,1852.98 1336.11,1851.8 ; 1336.19,1825.15 1336.19,1852.29 ; 1336.39,1825.41 1336.39,1824.94 1341.87,1819.46 ; 1342.07,1818.88 1342.22,1788.18 1373.84,1770.59 1373.84,1751.53 ; 1399.62,1874.64 1399.62,1881.39 1404.63,1886.4
  text "B" at 476.63,1281 h25
  text "A" at 842.58,1172.24 h25
  text "A" at 1358.06,133.88 h25
  text "B" at 135.4,130.17 h25
  text ".Layer_Name" at 577,-858.49 h60
Bottom Overlay:
  circle w10: c737.61,1263.72 r27.61
  circle w10: c386.79,1816.07 r23.67
  lines w5: 674.64,2182.02 cw(c722.95,2146.83) 678.6,2106.75 ; 973.69,2184.55 cw(c1022,2149.36) 977.66,2109.28
  lines w6: 74.88,1862.02 95.68,1862.02 ; 102,1891 123.07,1891 ; 239.73,1886 239.21,1886.55 240.13,1924.69 369,1925.99 369,1958 390.97,1958 392.27,1997 465,1997.41 465,2015 ; 250.99,1820.87 306.45,1820.87 306.45,1857 338.96,1857 ; 320,1844 353.89,1818.19 ; 467.02,2256 475.02,2264 475.13,2264 ; 477,2264 481,2264 ; 488,2040.21 588.08,2040.74 ; 543.84,2004.37 588.08,2005.09 588.08,2012 588.08,2038.38 ; 599.97,1856.23 607.86,1848.33 617,1848.33 ; 705.49,2034.36 711.78,2045.32 723.02,2046 ; 736.98,1928.06 736.98,1923.02 745.73,1914.27 748.73,1914.27 ; 782,2206 789.12,2198.1 ; 1063.6,1976.8 1062.27,2084.22 1100.05,2110.49 1100.34,2134.65 ; 1082.57,2202.75 1090.09,2195.23 ; 1124.36,2224.02 1154.65,2224.02 1163.25,2215.43 ; 1143.25,1846.77 1145.93,1849.44 ; 1150,1838 1186.53,1838 1193,1844.47 1193,1938.92 1231,1976.92 1231,2003.81 1241.19,2014 1241.19,2125.84 1251.33,2135.98 1251.33,2175.33 1258.69,2182.69 ; 1194.51,1954.3 1217.62,1977.4 1217.62,2007 ; 1145.93,1849.44 1145.93,1938 1131.99,1951.94 1104.21,1951.94 983.2,1951.94 970.57,1939.31 970.57,1854.26 984.5,1840.33 1136.82,1840.33 1145.93,1849.44 ; 524.75,1094.67 554.42,1065 663.23,1065 728.23,1130 845.74,1130 925.08,1209.34 949.1,1233.36 949.1,1284.9 942,1292 808,1292 794.09,1305.91 712.63,1305.91 688.15,1281.43 688.15,1207.15 674.74,1193.74 555.74,1193.74 524.75,1162.75 524.75,1094.67
  text "A" at 378.86,1804.58 h25
  text "A" at 729.82,1251.95 h25
  text "'.PRJ_Number'.PCB_Rev" at 391.1,452.5 h100.27 r270
  text "J6" at 294,243 h25
  text "J4" at 453.97,242.85 h25
  text "J3" at 1043.65,232.98 h25
  text "J5" at 1313.44,136.8 h25
  text "J8" at 905.46,109.55 h25
  text ".Layer_Name" at 577,-858.49 h60
Top Paste:
  text ".Layer_Name" at 577,-858.49 h60
Bottom Paste:
  text ".Layer_Name" at 577,-858.49 h60
Top Solder:
  region: 1163.21,1367.69 1276.29,1367.69 1276.48,1367.5 1276.48,1333.19 1276.29,1333 1276.29,1289.39 1163.21,1289.39
  region: 848.13,1363.18 985.92,1363.18 985.92,1309.06 848.13,1309.06
  region: 531.5,1367.67 669.29,1367.67 669.29,1289.37 531.5,1289.37
  region: 196.85,1324.65 196.85,1368.11 324.8,1368.11 344.49,1348.43 344.49,1289.37 232.13,1289.37
  text ".Layer_Name" at 577,-858.49 h60
  text ".Layer_Name" at 577,-858.49 h60
Bottom Solder:
  text ".Layer_Name" at 577,-858.49 h60
Drill Guide:
  text ".Layer_Name" at 577,-858.49 h60
M1 Board Outline:
  lines w8: 1448.82,0 0,0 0,2299.21 1448.82,2299.21 ; 1448.82,0 1448.82,2299.21 ; 1448.82,0 1448.82,0 ; 1448.82,2299.21 1448.82,2299.21
  text ".Layer_Name" at 578.99,-853.8 h50
M2 Board Dimensions:
  rectangle: 0,-275 125,-150
  rectangle: 125,-400 500,-275
  lines w8: 0,-275 1000,-275 ; 125,-400 125,-150 ; 250,-400 250,-150 ; 500,-400 500,-150 ; 750,-400 750,-150 ; 0,-400 1000,-400 1000,-150 0,-150 0,-400
M3 3D STEP Top:
  text ".Layer_Name" at 577,-858.49 h60
M4 3D STEP Bottom:
  text ".Layer_Name" at 577,-858.49 h60
M5 Assembly Top:
  circle w10: c31.9,488.74 r6.93
  circle w10: c612.5,305.01 r6.93
  circle w10: c794.17,460.91 r6.93
  circle w10: c863.47,592.25 r6.93
  circle w10: c104.79,1400.16 r6.93
  circle w10: c433.21,1399.48 r6.93
  circle w10: c748.5,1402.64 r6.93
  circle w10: c1068.21,1400.35 r6.93
  circle w10: c1185.97,1812.33 r6.93
  circle w10: c976.07,1923.43 r6.93
  circle w10: c826.11,1831.3 r6.93
  circle w10: c503.81,1808.26 r6.93
  circle w10: c176.12,1808.4 r6.93
  lines w6: 149.16,2111 149.16,2133 150,2154 176,2154 200,2154 205.02,2160.62 205.02,2181 ; 165,2048 231,2049.38 238.06,2054.94 250,2054.94 252,2057.82 259,2067 259,2091 262.32,2095 ; 263.96,2096.95 268,2101.8 268,2113 268,2157.09 281.95,2169.83 ; 297,2096.69 297,2124 ; 340.41,1362 373,1376.98 374.19,1392.06 ; 386.59,2111 402,2098 ; 409,1764 409,1795 420.8,1812 421.55,1834 ; 416,1936 414.8,1998 427.55,1998 527,1997 527.65,1937 ; 436,1831 495,1831 ; 622,2031 622,1886 660,1886 722,1886 742,1874 743,1751 ; 680,1358 678,1307 696,1278 746,1278 787,1244 798.26,1234.47 801,1091.52 848.43,1091.52 851,1250.02 ; 681.01,2045.68 732,2045.68 734,1901 ; 689,1057 689,1029.74 699,1022 747,1022 755,1015 ; 712.5,1343.37 713.75,1355 732.43,1370 842.62,1370 ; 759,1884 757.36,2032 772.78,2032 878,2031 878,1987 880,1889 1041,1887.73 1056,1866.68 1057,1755 ; 795,1665 795,1777 ; 1009,1544 1018,1554 1310.95,1554 1330,1526 1407,1526 1407,1432 1332,1430 ; 1146,2060.94 1148,1917 1152.94,1917 1156.67,1917.04 1298.6,1917 1298.6,1886 1298.6,1850.13 1304,1842.39 1339.3,1841.97 1352,1824 1352,1746 ; 1257,2059 1258,1919
  lines w10: -292,-930.17 6308,-930.17 ; -292,-726.83 6310,-726.83 ; -292,-523.5 -292,-1133.5 3713,-1133.5 6310,-1133.5 6310,-523.5 -291.5,-523.5 -291.5,-1133.5 1284,-1133.5 ; 2173,-1133.5 2173,-523.5 ; 3440,-726.83 3440,-523.5 ; 4280,-726.83 4280,-523.5 ; 4902,-1140 4902,-937.17
  text "COMPONENTS MARKED 'DNP' SHOULD NOT BE POPULATED." at 1153.5,-318.5 h60
  text "ASSEMBLY VARIANT:" at 1153,-434 h60
  text ".VariantName" at 2189,-434 h60
  text "PCB VIEWED FROM TOP SIDE" at -228.5,-655.67 h60
  text "BOARD #:" at 2248,-655.67 h60
  text ".PRJ_Number" at 2793.5,-655.67 h60
  text "REV:" at 3638,-655.67 h60
  text ".PCB_Rev" at 3929.5,-655.67 h60
  text "SVN REV:" at 4476,-655.67 h60
  text ".VersionControl_RevNumber" at 4982,-655.67 h60
  text "TID #:" at 2248,-859 h60
  text ".Layer_Name" at 70.76,-860.34 h50
  text "N/A" at 2586.09,-861 h60
  text "GENERATED    :" at 2250,-1064.34 h60
  text ".Print_Date" at 3119.5,-1064.34 h60
  text ".Print_Time" at 3848.5,-1064.34 h60
  text "TEXAS INSTRUMENTS" at 5113,-1064.34 h60
M6 Assembly Bottom:
  circle w10: c948.72,111.03 r6.14
  circle w10: c1253.12,1995.87 r6.14
  circle w10: c1283.72,1922.32 r6.14
  circle w10: c1268.84,1819.7 r6.14
  circle w10: c966.48,1818.32 r6.14
  circle w10: c674.67,1974.93 r6.14
  circle w10: c633.71,1784.04 r6.14
  circle w10: c307.79,1783.96 r6.14
  circle w10: c116.6,1812.76 r6.14
  circle w10: c1279.55,879.63 r6.14
  circle w10: c1114.41,671.35 r6.14
  circle w10: c1114.83,545.88 r6.14
  circle w10: c1134.83,1139.31 r31.91
  circle w10: c819,1879 r31.91
  circle w3: c315.43,2199.99 r6.21
  lines w6: 52,1913 53,1799 53,1796.12 55.67,1796.12 ; 52,1914.83 52,1917.27 68.83,1934.11 ; 54.13,1797.58 54.13,1795.9 63.03,1787 113,1787 137,1811 137,1812 ; 70.41,1934.11 113.89,1934.11 ; 138.2,1812 368,1811 ; 212.73,1936 342.1,1936 360,1953.9 360,2072.49 377.52,2090 385,2090 ; 370.05,1811 370.05,1811.05 402,1843 ; 386,2090 496,2090 ; 403.11,1843.65 407,1843.65 658,1843.65 746.65,1843.65 767,1864 ; 668,2055 753.2,2055 774,2034.2 ; 742,2208 691.29,2208 683,2216.29 683,2273 689,2279 785,2279 790,2279 794,2275 794.1,2275 797.94,2271.16 797.94,2200.94 ; 775,1916.83 775,2032 ; 779,2194 782,2194 802,2174 959,2174 966,2167 966,2043 974.8,2034.2 1091.16,2034.2 1102.59,2022.77 1102.59,1941.59 1093.28,1932.27 982.21,1932.27 957,1957.48 957,2018.59 972.42,2034 ; 938,1043 938,1069.85 913.85,1094 777,1094 763,1080 646,1080 573,1007 165,1007 113.89,1058.11 113.89,1175.89 131,1193 197,1193 212.73,1208.73 212.73,1240.73 244,1272 357,1272 376,1253 376,1206.94 398.94,1184 611,1184 633,1206 633,1251 664,1282 894,1282 915,1303 915,1353 929,1367 1119,1367 1136.38,1349.62 1136.38,1310.62 1193,1254 1344,1254 1383,1215 ; 939,1040 959,1021 ; 957.48,1022.44 1163.56,1022.44 1220,966 1355,966 1383,994 1383,1215 ; 1195.33,771 1229,771 1254,796 1254,842 1274,862 ; 1196,478 1196,431 1219,408 1263.4,408 ; 1265.33,408 1267,408 1267,407.4 1277,397.4 ; 1275,862 1290,862 ; 1383,1038 1383,1215
  lines w10: -292.5,-727.33 6309.5,-727.33 ; -290.5,-930.67 6309.5,-930.67 ; 1115.5,-1140.5 1115.5,-937.67 ; 1737.5,-727.33 1737.5,-524 ; 2577.5,-727.33 2577.5,-524 ; 3844.5,-1134 3844.5,-524 ; 4733.5,-1134 6309,-1134 6309,-524 -292.5,-524 -292.5,-1134 2304.5,-1134 6309.5,-1134 6309.5,-524
  text "A" at 810,1870 h25
  text "A" at 1125.83,1130.31 h25
  text "COMPONENTS MARKED 'DNP' SHOULD NOT BE POPULATED." at 6102,-318 h60
  text ".VariantName" at 5058,-434 h60
  text "ASSEMBLY VARIANT:" at 6097,-434 h60
  text ".VersionControl_RevNumber" at 1035.5,-656.17 h60
  text "SVN REV:" at 1541.5,-656.17 h60
  text ".PCB_Rev" at 2088,-656.17 h60
  text "REV:" at 2379.5,-656.17 h60
  text ".PRJ_Number" at 3224,-656.17 h60
  text "BOARD #:" at 3769.5,-656.17 h60
  text "PCB VIEWED FROM BOTTOM SIDE" at 6246,-656.17 h60
  text "N/A" at 3389.49,-859.88 h60
  text "TID #:" at 3769.5,-859.5 h60
  text ".Layer_Name" at 5543.09,-868.34 h50
  text "TEXAS INSTRUMENTS" at 904.5,-1064.84 h60
  text ".Print_Time" at 2169,-1064.84 h60
  text ".Print_Date" at 2898,-1064.84 h60
  text "GENERATED    :" at 3767.5,-1064.84 h60
M9 Title Sheet:
  drawing of 57 lines, arcs and shapes, not listed
  text "1" at 739.84,8036.5 h70
  text "2" at 3235.5,8036.5 h70
  text "3" at 5724.84,8036.5 h70
  text "4" at 8231.51,8036.5 h70
  text "5" at 10730.5,8036.5 h70
  text "6" at 13235.5,8036.5 h70
  text "A" at -416.5,6893.5 h70
  text "A" at 14383.5,6893.5 h70
  text "B" at -416.5,4513.5 h70
  text "B" at 14383.5,4513.5 h70
  text "C" at -416.5,2138.5 h70
  text "C" at 14383.5,2138.5 h70
  text "PROJECT TITLE:" at 11343.5,277.5 h45
  text ".PRJ_Title" at 11393.5,144.17 h70
  text "DESIGNED FOR:" at 11343.5,-23.5 h45
  text ".PRJ_Customer" at 11393.5,-163.5 h70
  text "D" at -416.5,-231.5 h70
  text "D" at 14383.5,-231.5 h70
  text "FILE NAME:" at 11343.5,-323.5 h45
  text ".PCB_File_Name_No_Path" at 11393.5,-443.5 h70
  text "Texas Instruments (TI) and/or its licensors do not warrant the accuracy or completeness of this specification" at 6374,-605.34 h45
  text "ENGINEER:" at 11343.5,-613.5 h45
  text "LAYOUT BY:" at 12848.5,-613.5 h45
  text "or any information contained therein. TI and/or its licensors do not warrant that this design will meet" at 6329.02,-718 h45
  text ".PRJ_Engineer" at 11393.5,-768.49 h70
  text ".PCB_Layout" at 12899,-768.49 h70
  text "the specifications, will be suitable for your application or fit for any particular purpose, or will operate in" at 6329.02,-830.67 h45
  text "ALTIUM DESIGNER VERSION:" at 12848.5,-923.5 h45
  text "an implementation. TI and/or its licensors do not warrant that the design is production worthy. You should" at 6329.02,-943.33 h45
  text "completely validate and test your design implementation to confirm the system functionality for your application." at 6374,-1056 h45
  text ".print_Scale" at 11393.5,-1056.83 h70
  text ".Application_BuildNumber" at 12899,-1056.83 h70
  text "1" at 739.84,-1263.5 h70
  text "2" at 3235.5,-1263.5 h70
  text "3" at 5724.84,-1263.5 h70
  text "4" at 8231.51,-1263.5 h70
  text "5" at 10730.5,-1263.5 h70
  text "6" at 13235.5,-1263.5 h70
M10 Fab Notes:
  drawing of 189 lines, arcs and shapes, not listed
  text "DESIGN INFORMATION" at 12382.02,6356.17 h60
  text "MIN. TRACK WIDTH:" at 11737.46,6224.05 h60
  text "6" at 12833.7,6224.05 h60
  text "MIL" at 12988.46,6224.05 h60
  text "4.921" at 12700,6107 h60
  text "MIN. CLEARANCE:" at 11737.46,6099.92 h60
  text "MIL" at 12988.46,6099.92 h60
  text "MIN. VIA PAD SIZE:" at 11737.46,5975.8 h60
  text "20" at 12803.71,5975.8 h60
  text "MIL" at 12988.46,5975.8 h60
  text "0.05mm (2MIL)" at 12432.46,5845.9 h60
  text "MINIMUM ANNULAR RING" at 11408.23,5837.67 h60
  text "EXTERNAL" at 13140.46,5837.67 h60
  text "PER" at 11608.23,5727.55 h60
  text "IPC-D-275 CLASS 2 LEVEL C" at 11828.23,5727.54 h60
  text "MIL, HOLES" at 13316.46,5627.07 h60
  text "+/-" at 12924,5618.48 h60
  text "+/-" at 13778,5618.48 h60
  text "REGISTRATION TOLERANCES:" at 11408.23,5617.42 h60
  text "METAL" at 12608,5617.42 h60
  text "5" at 13184.2,5617.42 h60
  text "3" at 14017.2,5617.42 h60
  text "MIL" at 14133.46,5617.42 h60
  text "HOLE SIZE TOLERANCE (UNLESS OTHERWISE SPECIFIED):" at 11408.23,5519.1 h60
  text "+/-" at 13778,5516.23 h60
  text "3" at 14017.2,5515.17 h60
  text "MIL" at 14133.46,5515.17 h60
  text "MATERIAL:" at 11333.46,5377.52 h60
  text "FR-4 High Tg" at 12319.9,5249 h60
  text "X" at 12175.47,5241.01 h60
  text "FR-4" at 11754.46,5236.49 h60
  text "OTHER" at 13242.46,5236.49 h60
  text ".Total_Thickness(Board Layer Stack)" at 12074.56,5093.46 h60
  text "+/-10mils" at 12479,5093.46 h60
  text "X" at 11954.47,5091.01 h60
  text "THICKNESS:" at 11408.23,5085.24 h60
  text "OTHER" at 13359.46,5085.24 h60
  text "TOLERANCE:" at 11408.23,4946.92 h60
  text "X" at 12256.47,4946.92 h60
  text "ANSI IPC-6012 TYPE 3 CLASS 2" at 12434.48,4946.92 h60
  text "OTHER +/-" at 12434.46,4802.73 h60
  text "BOW & TWIST:" at 11408.23,4657.54 h60
  text "X" at 12256.47,4657.54 h60
  text "ANSI IPC-6012 TYPE 3 CLASS 2" at 12434.48,4657.54 h60
  text "OTHER +/-" at 12434.46,4510.85 h60
  text "DRILLING:" at 11333.46,4380.23 h60
  text "NC_DRILL FILES" at 13094.46,4275.04 h60
  text "REFERENCE:" at 11408.23,4271.1 h60
  text "X" at 12065.47,4271.01 h60
  text "AS SHOWN" at 12243.46,4271.1 h60
  text "X" at 12966.47,4271.1 h60
  text "OTHER" at 13392.46,4128.85 h60
  text "PTH COPPER THICKNESS:" at 11407.91,4125.32 h60
  text "X" at 12547.14,4125.32 h60
  text "20-30 um" at 12675.14,4125.32 h60
  text "BOARD FINISH:" at 11333.46,3977.73 h60
  text "SILKSCREEN:" at 11488.68,3867.6 h60
  text "X" at 12446.47,3867.6 h60
  text "TOP" at 12563.46,3867.6 h60
  text "X" at 12956.47,3867.6 h60
  text "BOTTOM" at 13074.46,3867.6 h60
  text "SILKSCREEN COLOR:" at 11488.68,3712.41 h60
  text "X" at 12445.47,3712.41 h60
  text "WHITE" at 12563.46,3712.41 h60
  text "OTHER" at 13074.46,3712.41 h60
  text "X" at 12576.47,3568.96 h60
  text "GREEN" at 12694.46,3568.96 h60
  text "OTHER" at 13312.46,3568.96 h60
  text "SOLDER RESIST COLOR:" at 11488.68,3562.1 h60
  text "X" at 12576.47,3414.71 h60
  text "MATTE" at 12694.46,3414.71 h60
  text "SEMI-GLOSS" at 13312,3414.07 h60
  text "IMMERSION GOLD (ENIG)" at 12394.46,3241.94 h60
  text "ENEPIG" at 13732,3234.72 h60
  text "SURFACE FINISH:" at 11333.46,3233.72 h60
  text "X" at 12216.47,3233.72 h60
  text "IMM. TIN/SILVER OR EQUIV" at 11663,3096.4 h60
  text "OTHER" at 13094.46,3092.47 h60
  text "ARRAY/PANEL:" at 11333.46,2937.09 h60
  text "X" at 12214.09,2929 h60
  text "CUT AND TRIM PER M1 BOARD OUTLINE" at 12394.46,2928.87 h60
  text "N.C. ROUTE" at 12394.46,2792.9 h60
  text "V. SCORE" at 13260.46,2792.9 h60
  text "CERTIFICATION:" at 11333.46,2663.77 h60
  text "MATERIALS AND WORKMANSHIP FOR ALL PCBS" at 12058.46,2663.77 h60
  text "TO MEET OR EXCEED THE REQUIREMENTS OF:" at 12058.46,2569.71 h60
  text "X" at 11695.97,2441.08 h60
  text "ANSI IPC-A-600F CLASS ->" at 11823.96,2441.08 h60
  text "X" at 13471.97,2441.08 h60
  text "2" at 13581.96,2441.08 h60
  text "1" at 13266.96,2439.58 h60
  text "3" at 13935.96,2439.58 h60
  text "FAB NOTES" at 3519.13,2356.71 h70
  text "X" at 12507.97,2293.39 h60
  text "RoHS" at 12635.96,2293.39 h60
  text "OTHER" at 13280.37,2293.39 h60
  text "PER ORDER" at 13677.42,2293.39 h60
  text "1.ALL VIAS ARE TENTED IN BOTH SIDE UNLESS OTHERWISE MASK OPENED IN GERBERS." at 3493.65,2172.92 h70
  text "ALL BOARDS MUST MEET OR EXCEED UL94-V0 REQUIREMENTS." at 11361,2139.57 h60
  text "PCB MUST BEAR THE UL94V-0 UL REGISTERED MATERIAL ID NUMBER" at 11361,2023.5 h60
  text "2.VENDOR MAY ADJUST SOLDERMASK WHEREVER SOLDERMASK PADS ARE THE SAME SIZE (1: 1)" at 3489.32,2022.52 h70
  text "ADDITIONAL REQUIREMENTS:" at 11333.46,1854.08 h60
  text "AS PER THE MANUFACTURING CAPABILITIES AND ALL OTHER SOLDER MASK PADS SHALL NOT BE MODIFIED ." at 3632.67,1852.07 h70
  text "MICROSECTION:" at 11408.23,1746.95 h60
  text "YES" at 12313.96,1746.95 h60
  text "PROVIDED NO ADJACENT COPPER IS EXPOSED AND NO CONFLICT IS PRODUCED WITH ANY STATED \" VIA" at 3633.06,1680.21 h70
  text "REQUIRED" at 13175.46,1602.62 h60
  text "BARE BOARD ELEC. TEST:" at 11408.23,1599.76 h60
  text "NONE" at 12713.96,1599.76 h60
  text "X" at 13057.47,1599.76 h60
  text "PER ORDER" at 13767.46,1599.76 h60
  text "TENTING / COVERING \" REQUIREMENTS." at 3619.27,1514.78 h70
  text "XX MIL VIAS REQUIRE NON-CONDUCTIVE FILL AND PLANARIZE" at 11576.38,1394.82 h59
  text "3.ALL DIMENSIONS ARE IN MM." at 3488.68,1348.31 h70
  text "XX MIL VIAS REQUIRE CONDUCTIVE FILL AND PLANARIZE" at 11584.38,1290.84 h60
  text "4. ALL VIAS NEED TO BE FILLED WITH CONDUCTIVE EPOXY-RESIN AND OVERPLATE WITH" at 3489.6,1146.08 h70
  text "OUTER XX MIL TRACES REQUIRE 50 OHM SINGLE-ENDED IMPEDANCE" at 11583.39,1127.46 h58
  text "COPPER. SURFACE MUST BE FLAT, FLATNESS TOLERANCE IS +0.000/-0.001\" ." at 3627.04,988.65 h70
  text "LAYER 2 & 3 (INNER LAYERS) XX MIL WIDE, XX MIL SPACE / TRACES REQUIRE 100 OHM DIFFERENTIAL IMPEDANCE" at 11575.39,891.74 h60
  text "MINIMUM ANNULAR RING REQUIREMENT IS WAIVED FOR FILLED VIAS." at 3623.83,834.11 h70
  text "5.THIS IS NOT AN IMPEDANCE CONTROLLED BOARD" at 3523,674 h70
M11 Gerber Information:
  lines w10: -292,-930.17 6308,-930.17 ; -292,-726.83 6310,-726.83 ; -292,-523.5 -292,-1133.5 3713,-1133.5 6310,-1133.5 6310,-523.5 -291.5,-523.5 -291.5,-1133.5 1284,-1133.5 ; 2173,-1133.5 2173,-523.5 ; 3440,-726.83 3440,-523.5 ; 4280,-726.83 4280,-523.5 ; 4902,-1140 4902,-937.17
  text "ALL ARTWORK VIEWED FROM TOP SIDE" at -228.5,-655.67 h60
  text "BOARD #:" at 2248,-655.67 h60
  text ".PRJ_Number" at 2793.5,-655.67 h60
  text "REV:" at 3638,-655.67 h60
  text ".PCB_Rev" at 3929.5,-655.67 h60
  text "SVN REV:" at 4476,-655.67 h60
  text ".VersionControl_RevNumber" at 4982,-655.67 h60
  text "LAYER NAME =" at -228.5,-858.49 h60
  text "TID #:" at 2248,-859 h60
  text "N/A" at 2626.94,-864.43 h60
  text "GENERATED    :" at 2250,-1064.34 h60
  text ".Print_Date" at 3119.5,-1064.34 h60
  text ".Print_Time" at 3848.5,-1064.34 h60
  text "TEXAS INSTRUMENTS" at 5113,-1064.34 h60
M12 Stackup:
  drawing of 919 lines, arcs and shapes, not listed
  text "STACK UP" at 5906.69,7667.87 h100
  text "Layer" at 5554.67,7507 h60
  text "Name" at 5964.58,7507 h60
  text "Material" at 6894.33,7507 h60
  text "Thickness" at 7754.09,7507 h60
  text "Constant" at 8403.93,7507 h60
  text "Board Layer Stack" at 8973.79,7507 h60
  text "Top Overlay" at 5964.58,7387 h60
  text "Top Solder" at 5964.58,7267 h60
  text "Solder Resist" at 6894.33,7267 h60
  text "0.40mil" at 7754.09,7267 h60
  text "3.5" at 8403.93,7267 h60
  text "1" at 5554.67,7147 h60
  text "Top Layer" at 5964.58,7147 h60
  text "COPPER" at 6894.33,7147 h60
  text "2.76mil" at 7754.09,7147 h60
  text "Dielectric 1" at 5964.58,7027 h60
  text "FR-4 High Tg" at 6894.33,7027 h60
  text "2.80mil" at 7754.09,7027 h60
  text "4.1" at 8403.93,7027 h60
  text "2" at 5554.67,6907 h60
  text "GND1" at 5964.58,6907 h60
  text "COPPER" at 6894.33,6907 h60
  text "4.13mil" at 7754.09,6907 h60
  text "Dielectric 2" at 5964.58,6787 h60
  text "FR-4 High Tg" at 6894.33,6787 h60
  text "2.80mil" at 7754.09,6787 h60
  text "4.1" at 8403.93,6787 h60
  text "3" at 5554.67,6667 h60
  text "PWR1" at 5964.58,6667 h60
  text "COPPER" at 6894.33,6667 h60
  text "4.13mil" at 7754.09,6667 h60
  text "Dielectric 3" at 5964.58,6547 h60
  text "FR-4 High Tg" at 6894.33,6547 h60
  text "2.80mil" at 7754.09,6547 h60
  text "4.1" at 8403.93,6547 h60
  text "4" at 5554.67,6427 h60
  text "PWR2" at 5964.58,6427 h60
  text "COPPER" at 6894.33,6427 h60
  text "4.13mil" at 7754.09,6427 h60
  text "Dielectric 4" at 5964.58,6307 h60
  text "FR-4 High Tg" at 6894.33,6307 h60
  text "2.80mil" at 7754.09,6307 h60
  text "4.1" at 8403.93,6307 h60
  text "5" at 5554.67,6187 h60
  text "PWR3" at 5964.58,6187 h60
  text "COPPER" at 6894.33,6187 h60
  text "4.13mil" at 7754.09,6187 h60
  text "Dielectric 5" at 5964.58,6067 h60
  text "FR-4 High Tg" at 6894.33,6067 h60
  text "2.80mil" at 7754.09,6067 h60
  text "4.1" at 8403.93,6067 h60
  text "6" at 5554.67,5947 h60
  text "GND2" at 5964.58,5947 h60
  text "COPPER" at 6894.33,5947 h60
  text "4.13mil" at 7754.09,5947 h60
  text "Dielectric 6" at 5964.58,5827 h60
  text "FR-4 High Tg" at 6894.33,5827 h60
  text "2.80mil" at 7754.09,5827 h60
  text "4.1" at 8403.93,5827 h60
  text "7" at 5554.67,5707 h60
  text "GND3/SIG1" at 5964.58,5707 h60
  text "COPPER" at 6894.33,5707 h60
  text "4.13mil" at 7754.09,5707 h60
  text "Dielectric 7" at 5964.58,5587 h60
  text "FR-4 High Tg" at 6894.33,5587 h60
  text "2.80mil" at 7754.09,5587 h60
  text "4.1" at 8403.93,5587 h60
  text "8" at 5554.67,5467 h60
  text "SIG2" at 5964.58,5467 h60
  text "COPPER" at 6894.33,5467 h60
  text "4.13mil" at 7754.09,5467 h60
  text "Dielectric8" at 5964.58,5347 h60
  text "FR-4 High Tg" at 6894.33,5347 h60
  text "46.22mil" at 7754.09,5347 h60
  text "4.8" at 8403.93,5347 h60
  text "9" at 5554.67,5227 h60
  text "SIG3" at 5964.58,5227 h60
  text "COPPER" at 6894.33,5227 h60
  text "4.13mil" at 7754.09,5227 h60
  text "Dielectric 9" at 5964.58,5107 h60
  text "FR-4 High Tg" at 6894.33,5107 h60
  text "2.80mil" at 7754.09,5107 h60
  text "4.1" at 8403.93,5107 h60
  text "10" at 5554.67,4987 h60
  text "GND3/SIG4" at 5964.58,4987 h60
  text "COPPER" at 6894.33,4987 h60
  text "4.13mil" at 7754.09,4987 h60
  text "Dielectric 10" at 5964.58,4867 h60
  text "FR-4 High Tg" at 6894.33,4867 h60
  text "2.80mil" at 7754.09,4867 h60
  text "4.1" at 8403.93,4867 h60
  text "11" at 5554.67,4747 h60
  text "GND5" at 5964.58,4747 h60
  text "COPPER" at 6894.33,4747 h60
  text "4.13mil" at 7754.09,4747 h60
  text "Dielectric 11" at 5964.58,4627 h60
  text "FR-4 High Tg" at 6894.33,4627 h60
  text "2.80mil" at 7754.09,4627 h60
  text "4.1" at 8403.93,4627 h60
  text "12" at 5554.67,4507 h60
  text "PWR4" at 5964.58,4507 h60
  text "COPPER" at 6894.33,4507 h60
  text "4.13mil" at 7754.09,4507 h60
  text "Dielectric 12" at 5964.58,4387 h60
  text "FR-4 High Tg" at 6894.33,4387 h60
  text "2.80mil" at 7754.09,4387 h60
  text "4.1" at 8403.93,4387 h60
  text "13" at 5554.67,4267 h60
  text "PWR5" at 5964.58,4267 h60
  text "COPPER" at 6894.33,4267 h60
  text "4.13mil" at 7754.09,4267 h60
  text "Dielectric 13" at 5964.58,4147 h60
  text "FR-4 High Tg" at 6894.33,4147 h60
  text "2.80mil" at 7754.09,4147 h60
  text "4.1" at 8403.93,4147 h60
  text "14" at 5554.67,4027 h60
  text "GND6" at 5964.58,4027 h60
  text "COPPER" at 6894.33,4027 h60
  text "4.13mil" at 7754.09,4027 h60
  text "Dielectric 14" at 5964.58,3907 h60
  text "FR-4 High Tg" at 6894.33,3907 h60
  text "2.80mil" at 7754.09,3907 h60
  text "4.1" at 8403.93,3907 h60
  text "15" at 5554.67,3787 h60
  text "GND7" at 5964.58,3787 h60
  text "COPPER" at 6894.33,3787 h60
  text "4.13mil" at 7754.09,3787 h60
  text "Dielectric 15" at 5964.58,3667 h60
  text "FR-4 High Tg" at 6894.33,3667 h60
  text "2.80mil" at 7754.09,3667 h60
  text "4.1" at 8403.93,3667 h60
  text "16" at 5554.67,3547 h60
  text "Bottom Layer" at 5964.58,3547 h60
  text "COPPER" at 6894.33,3547 h60
  text "2.76mil" at 7754.09,3547 h60
  text "Bottom Solder" at 5964.58,3427 h60
  text "Solder Resist" at 6894.33,3427 h60
  text "0.40mil" at 7754.09,3427 h60
  text "3.5" at 8403.93,3427 h60
  text "Bottom Overlay" at 5964.58,3307 h60
  text "Total board thickness:" at 5554.67,3187 h60
  text "149.61mil" at 7754.09,3187 h60
  text "+/-10mils" at 8254.11,3180.32 h100
M13 Component Bodies Top:
  text ".Layer_Name" at 577,-858.49 h60
M14 Component Bodies Bottom:
  text ".Layer_Name" at 577,-858.49 h60
M15 Courtyards Top:
  text ".Layer_Name" at 577,-858.49 h60
M16 Courtyards Bottom:
  text ".Layer_Name" at 577,-858.49 h60
Drill Drawing:
  circle w10: c598.67,6917.34 r33.33
  lines w10: 565.34,7034.01 632.01,7034.01 632.01,7100.68 565.34,7100.68 565.34,7034.01 ; 565.34,7250.68 632.01,7250.68 598.67,7184.01 565.34,7250.68 ; 565.34,7334.01 598.67,7350.68 632.01,7334.01 615.34,7367.34 632.01,7400.68 598.67,7384.01 565.34,7400.68 582.01,7367.34 565.34,7334.01 ; 565.34,7500.68 582.01,7500.68 582.01,7484.01 615.34,7484.01 615.34,7500.68 632.01,7500.68 632.01,7534.01 615.34,7534.01 615.34,7550.68 582.01,7550.68 582.01,7534.01 565.34,7534.01 565.34,7500.68
  lines w12: 505.55,6839.01 4326.53,6839.01 ; 505.55,7589.01 4326.53,7589.01 ; 1056.42,6689.01 1056.42,7739.01 ; 1696.25,6689.01 1696.25,7739.01 ; 3041.86,6689.01 3041.86,7739.01 ; 3547.73,6689.01 3547.73,7739.01 ; 505.55,6689.01 4326.53,6689.01 4326.53,7739.01 505.55,7739.01 505.55,6689.01
  text "DRILL TABLE" at 445.09,7805 h50
  text "Symbol" at 595.55,7634.01 h72
  text "Quantity" at 1101.42,7634.01 h72
  text "Finished Hole Size" at 1741.25,7634.01 h72
  text "Plated" at 3086.86,7634.01 h72
  text "Hole Type" at 3592.73,7634.01 h72
  text "226" at 1101.42,7484.01 h60
  text "10.00mil (0.254mm)" at 1741.25,7484.01 h60
  text "PTH" at 3086.86,7484.01 h60
  text "Round" at 3592.73,7484.01 h60
  text "921" at 1101.42,7334.01 h60
  text "13.00mil (0.330mm)" at 1741.25,7334.01 h60
  text "PTH" at 3086.86,7334.01 h60
  text "Round" at 3592.73,7334.01 h60
  text "8" at 1101.42,7184.01 h60
  text "31.50mil (0.800mm)" at 1741.25,7184.01 h60
  text "PTH" at 3086.86,7184.01 h60
  text "Round" at 3592.73,7184.01 h60
  text "7" at 1101.42,7034.01 h60
  text "64.02mil (1.626mm)" at 1741.25,7034.01 h60
  text "PTH" at 3086.86,7034.01 h60
  text "Round" at 3592.73,7034.01 h60
  text "2" at 1101.42,6884.01 h60
  text "94.49mil (2.400mm)" at 1741.25,6884.01 h60
  text "NPTH" at 3086.86,6884.01 h60
  text "Round" at 3592.73,6884.01 h60
  text "1164 Total" at 1101.42,6734.01 h60
  text "TOLERANCE :-" at 497.65,6519.2 h50
  text "FOR 10  MIL DRILL  +0/-10 MIL" at 505.64,6401.09 h50
  text "FOR 13  MIL DRILL  +0/-13MIL" at 506.02,6295.81 h50
  text "FOR PTH +/- 3MIL" at 509.49,6196.98 h50
  text "FOR NPTH +/- 2MIL" at 509.49,6088.72 h50
  text "FAB LAYER" at 577,-858.49 h60
M17 Embedded Cavity:
  text ".Layer_Name" at 577,-858.49 h60
M18 Embedded Assembly:
  text ".Layer_Name" at 577,-858.49 h60
M19 Embedded Keepout:
  text ".Layer_Name" at 577,-858.49 h60

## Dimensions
0,-400 to 1000,-400 on M2 Board Dimensions
0,0 to 1448.82,0 on M2 Board Dimensions
0,0 to 0,2299.21 on M2 Board Dimensions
